VERSION 5.8 ;
BUSBITCHARS "[]" ;
DIVIDERCHAR "/" ;
UNITS
    DATABASE MICRONS 1000 ;
END UNITS

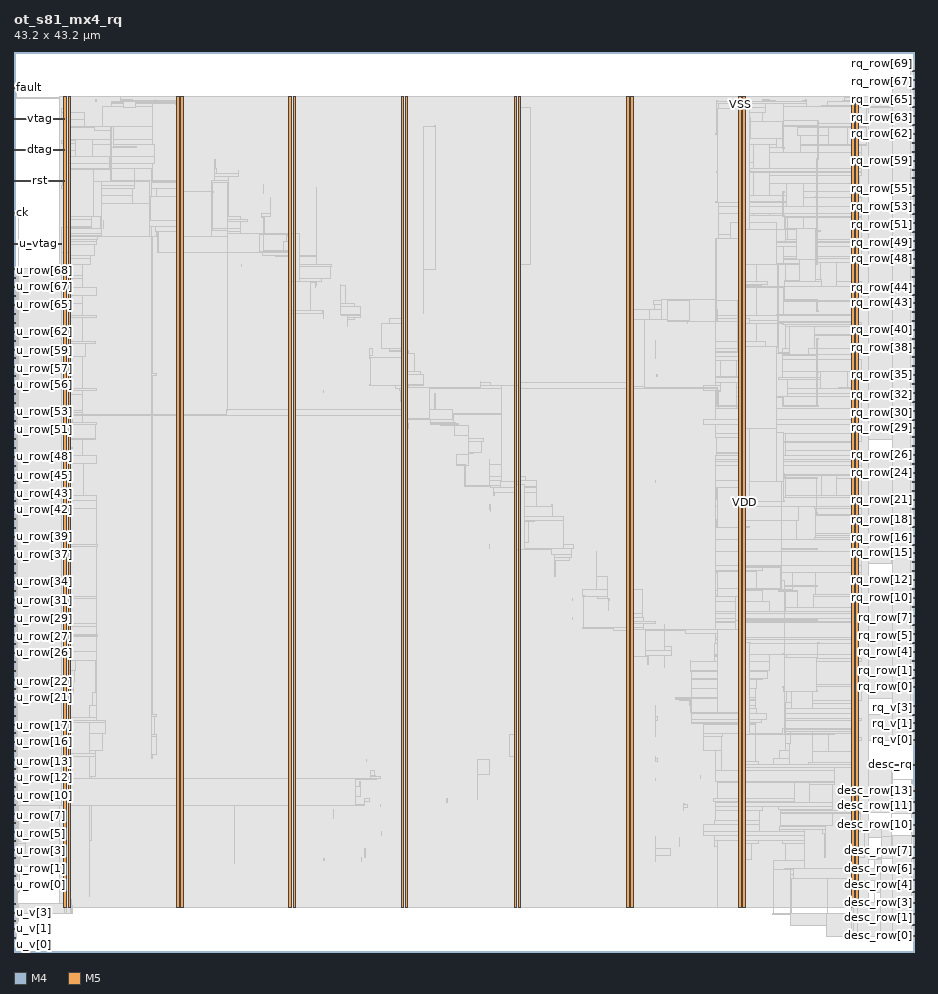
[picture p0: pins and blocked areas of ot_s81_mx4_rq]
MACRO ot_s81_mx4_rq
  FOREIGN ot_s81_mx4_rq 0 0 ;
  CLASS BLOCK ;
  SIZE 43.2 BY 43.2 ;
  PIN ck
    DIRECTION INPUT ;
    USE SIGNAL ;
    PORT
      LAYER M4 ;
        RECT  0 35.472 0.084 35.496 ;
    END
    PORT
      LAYER M4 ;
        RECT  0.06 35.472 0.227 35.496 ;
    END
  END ck
  PIN desc_row[0]
    DIRECTION INPUT ;
    USE SIGNAL ;
    PORT
      LAYER M4 ;
        RECT  43.116 0.768 43.2 0.792 ;
    END
  END desc_row[0]
  PIN desc_row[10]
    DIRECTION INPUT ;
    USE SIGNAL ;
    PORT
      LAYER M4 ;
        RECT  43.116 6.096 43.2 6.12 ;
    END
  END desc_row[10]
  PIN desc_row[11]
    DIRECTION INPUT ;
    USE SIGNAL ;
    PORT
      LAYER M4 ;
        RECT  43.116 6.672 43.2 6.696 ;
    END
  END desc_row[11]
  PIN desc_row[12]
    DIRECTION INPUT ;
    USE SIGNAL ;
    PORT
      LAYER M4 ;
        RECT  43.116 7.2 43.2 7.224 ;
    END
  END desc_row[12]
  PIN desc_row[13]
    DIRECTION INPUT ;
    USE SIGNAL ;
    PORT
      LAYER M4 ;
        RECT  43.116 7.728 43.2 7.752 ;
    END
  END desc_row[13]
  PIN desc_row[1]
    DIRECTION INPUT ;
    USE SIGNAL ;
    PORT
      LAYER M4 ;
        RECT  43.116 1.296 43.2 1.32 ;
    END
  END desc_row[1]
  PIN desc_row[2]
    DIRECTION INPUT ;
    USE SIGNAL ;
    PORT
      LAYER M4 ;
        RECT  43.116 1.824 43.2 1.848 ;
    END
  END desc_row[2]
  PIN desc_row[3]
    DIRECTION INPUT ;
    USE SIGNAL ;
    PORT
      LAYER M4 ;
        RECT  43.116 2.352 43.2 2.376 ;
    END
  END desc_row[3]
  PIN desc_row[4]
    DIRECTION INPUT ;
    USE SIGNAL ;
    PORT
      LAYER M4 ;
        RECT  43.116 2.88 43.2 2.904 ;
    END
  END desc_row[4]
  PIN desc_row[5]
    DIRECTION INPUT ;
    USE SIGNAL ;
    PORT
      LAYER M4 ;
        RECT  43.116 3.456 43.2 3.48 ;
    END
  END desc_row[5]
  PIN desc_row[6]
    DIRECTION INPUT ;
    USE SIGNAL ;
    PORT
      LAYER M4 ;
        RECT  43.116 3.984 43.2 4.008 ;
    END
  END desc_row[6]
  PIN desc_row[7]
    DIRECTION INPUT ;
    USE SIGNAL ;
    PORT
      LAYER M4 ;
        RECT  43.116 4.512 43.2 4.536 ;
    END
  END desc_row[7]
  PIN desc_row[8]
    DIRECTION INPUT ;
    USE SIGNAL ;
    PORT
      LAYER M4 ;
        RECT  43.116 5.04 43.2 5.064 ;
    END
  END desc_row[8]
  PIN desc_row[9]
    DIRECTION INPUT ;
    USE SIGNAL ;
    PORT
      LAYER M4 ;
        RECT  43.116 5.568 43.2 5.592 ;
    END
  END desc_row[9]
  PIN desc_rq
    DIRECTION INPUT ;
    USE SIGNAL ;
    PORT
      LAYER M4 ;
        RECT  43.116 8.976 43.2 9 ;
    END
    PORT
      LAYER M4 ;
        RECT  42.145 8.976 43.164 9 ;
    END
  END desc_rq
  PIN dtag
    DIRECTION OUTPUT ;
    USE SIGNAL ;
    PORT
      LAYER M4 ;
        RECT  0 38.496 0.084 38.52 ;
    END
    PORT
      LAYER M4 ;
        RECT  0.06 38.496 2.401 38.52 ;
    END
  END dtag
  PIN fault
    DIRECTION OUTPUT ;
    USE SIGNAL ;
    PORT
      LAYER M4 ;
        RECT  0 41.472 0.084 41.496 ;
    END
    PORT
      LAYER M4 ;
        RECT  0.06 41.472 0.137 41.496 ;
    END
  END fault
  PIN rq_row[0]
    DIRECTION OUTPUT ;
    USE SIGNAL ;
    PORT
      LAYER M4 ;
        RECT  43.116 12.72 43.2 12.744 ;
    END
  END rq_row[0]
  PIN rq_row[10]
    DIRECTION OUTPUT ;
    USE SIGNAL ;
    PORT
      LAYER M4 ;
        RECT  43.116 16.992 43.2 17.016 ;
    END
  END rq_row[10]
  PIN rq_row[11]
    DIRECTION OUTPUT ;
    USE SIGNAL ;
    PORT
      LAYER M4 ;
        RECT  43.116 17.424 43.2 17.448 ;
    END
  END rq_row[11]
  PIN rq_row[12]
    DIRECTION OUTPUT ;
    USE SIGNAL ;
    PORT
      LAYER M4 ;
        RECT  43.116 17.856 43.2 17.88 ;
    END
  END rq_row[12]
  PIN rq_row[13]
    DIRECTION OUTPUT ;
    USE SIGNAL ;
    PORT
      LAYER M4 ;
        RECT  43.116 18.288 43.2 18.312 ;
    END
  END rq_row[13]
  PIN rq_row[14]
    DIRECTION OUTPUT ;
    USE SIGNAL ;
    PORT
      LAYER M4 ;
        RECT  43.116 18.72 43.2 18.744 ;
    END
  END rq_row[14]
  PIN rq_row[15]
    DIRECTION OUTPUT ;
    USE SIGNAL ;
    PORT
      LAYER M4 ;
        RECT  43.116 19.152 43.2 19.176 ;
    END
  END rq_row[15]
  PIN rq_row[16]
    DIRECTION OUTPUT ;
    USE SIGNAL ;
    PORT
      LAYER M4 ;
        RECT  43.116 19.536 43.2 19.56 ;
    END
  END rq_row[16]
  PIN rq_row[17]
    DIRECTION OUTPUT ;
    USE SIGNAL ;
    PORT
      LAYER M4 ;
        RECT  43.116 19.968 43.2 19.992 ;
    END
  END rq_row[17]
  PIN rq_row[18]
    DIRECTION OUTPUT ;
    USE SIGNAL ;
    PORT
      LAYER M4 ;
        RECT  43.116 20.4 43.2 20.424 ;
    END
  END rq_row[18]
  PIN rq_row[19]
    DIRECTION OUTPUT ;
    USE SIGNAL ;
    PORT
      LAYER M4 ;
        RECT  43.116 20.832 43.2 20.856 ;
    END
  END rq_row[19]
  PIN rq_row[1]
    DIRECTION OUTPUT ;
    USE SIGNAL ;
    PORT
      LAYER M4 ;
        RECT  43.116 13.152 43.2 13.176 ;
    END
  END rq_row[1]
  PIN rq_row[20]
    DIRECTION OUTPUT ;
    USE SIGNAL ;
    PORT
      LAYER M4 ;
        RECT  43.116 21.264 43.2 21.288 ;
    END
  END rq_row[20]
  PIN rq_row[21]
    DIRECTION OUTPUT ;
    USE SIGNAL ;
    PORT
      LAYER M4 ;
        RECT  43.116 21.696 43.2 21.72 ;
    END
  END rq_row[21]
  PIN rq_row[22]
    DIRECTION OUTPUT ;
    USE SIGNAL ;
    PORT
      LAYER M4 ;
        RECT  43.116 22.128 43.2 22.152 ;
    END
  END rq_row[22]
  PIN rq_row[23]
    DIRECTION OUTPUT ;
    USE SIGNAL ;
    PORT
      LAYER M4 ;
        RECT  43.116 22.56 43.2 22.584 ;
    END
  END rq_row[23]
  PIN rq_row[24]
    DIRECTION OUTPUT ;
    USE SIGNAL ;
    PORT
      LAYER M4 ;
        RECT  43.116 22.992 43.2 23.016 ;
    END
  END rq_row[24]
  PIN rq_row[25]
    DIRECTION OUTPUT ;
    USE SIGNAL ;
    PORT
      LAYER M4 ;
        RECT  43.116 23.424 43.2 23.448 ;
    END
  END rq_row[25]
  PIN rq_row[26]
    DIRECTION OUTPUT ;
    USE SIGNAL ;
    PORT
      LAYER M4 ;
        RECT  43.116 23.856 43.2 23.88 ;
    END
  END rq_row[26]
  PIN rq_row[27]
    DIRECTION OUTPUT ;
    USE SIGNAL ;
    PORT
      LAYER M4 ;
        RECT  43.116 24.288 43.2 24.312 ;
    END
  END rq_row[27]
  PIN rq_row[28]
    DIRECTION OUTPUT ;
    USE SIGNAL ;
    PORT
      LAYER M4 ;
        RECT  43.116 24.72 43.2 24.744 ;
    END
  END rq_row[28]
  PIN rq_row[29]
    DIRECTION OUTPUT ;
    USE SIGNAL ;
    PORT
      LAYER M4 ;
        RECT  43.116 25.152 43.2 25.176 ;
    END
  END rq_row[29]
  PIN rq_row[2]
    DIRECTION OUTPUT ;
    USE SIGNAL ;
    PORT
      LAYER M4 ;
        RECT  43.116 13.536 43.2 13.56 ;
    END
  END rq_row[2]
  PIN rq_row[30]
    DIRECTION OUTPUT ;
    USE SIGNAL ;
    PORT
      LAYER M4 ;
        RECT  43.116 25.536 43.2 25.56 ;
    END
  END rq_row[30]
  PIN rq_row[31]
    DIRECTION OUTPUT ;
    USE SIGNAL ;
    PORT
      LAYER M4 ;
        RECT  43.116 25.968 43.2 25.992 ;
    END
  END rq_row[31]
  PIN rq_row[32]
    DIRECTION OUTPUT ;
    USE SIGNAL ;
    PORT
      LAYER M4 ;
        RECT  43.116 26.4 43.2 26.424 ;
    END
  END rq_row[32]
  PIN rq_row[33]
    DIRECTION OUTPUT ;
    USE SIGNAL ;
    PORT
      LAYER M4 ;
        RECT  43.116 26.832 43.2 26.856 ;
    END
  END rq_row[33]
  PIN rq_row[34]
    DIRECTION OUTPUT ;
    USE SIGNAL ;
    PORT
      LAYER M4 ;
        RECT  43.116 27.264 43.2 27.288 ;
    END
  END rq_row[34]
  PIN rq_row[35]
    DIRECTION OUTPUT ;
    USE SIGNAL ;
    PORT
      LAYER M4 ;
        RECT  43.116 27.696 43.2 27.72 ;
    END
  END rq_row[35]
  PIN rq_row[36]
    DIRECTION OUTPUT ;
    USE SIGNAL ;
    PORT
      LAYER M4 ;
        RECT  43.116 28.128 43.2 28.152 ;
    END
  END rq_row[36]
  PIN rq_row[37]
    DIRECTION OUTPUT ;
    USE SIGNAL ;
    PORT
      LAYER M4 ;
        RECT  43.116 28.56 43.2 28.584 ;
    END
  END rq_row[37]
  PIN rq_row[38]
    DIRECTION OUTPUT ;
    USE SIGNAL ;
    PORT
      LAYER M4 ;
        RECT  43.116 28.992 43.2 29.016 ;
    END
  END rq_row[38]
  PIN rq_row[39]
    DIRECTION OUTPUT ;
    USE SIGNAL ;
    PORT
      LAYER M4 ;
        RECT  43.116 29.424 43.2 29.448 ;
    END
  END rq_row[39]
  PIN rq_row[3]
    DIRECTION OUTPUT ;
    USE SIGNAL ;
    PORT
      LAYER M4 ;
        RECT  43.116 13.968 43.2 13.992 ;
    END
  END rq_row[3]
  PIN rq_row[40]
    DIRECTION OUTPUT ;
    USE SIGNAL ;
    PORT
      LAYER M4 ;
        RECT  43.116 29.856 43.2 29.88 ;
    END
  END rq_row[40]
  PIN rq_row[41]
    DIRECTION OUTPUT ;
    USE SIGNAL ;
    PORT
      LAYER M4 ;
        RECT  43.116 30.288 43.2 30.312 ;
    END
  END rq_row[41]
  PIN rq_row[42]
    DIRECTION OUTPUT ;
    USE SIGNAL ;
    PORT
      LAYER M4 ;
        RECT  43.116 30.72 43.2 30.744 ;
    END
  END rq_row[42]
  PIN rq_row[43]
    DIRECTION OUTPUT ;
    USE SIGNAL ;
    PORT
      LAYER M4 ;
        RECT  43.116 31.152 43.2 31.176 ;
    END
  END rq_row[43]
  PIN rq_row[44]
    DIRECTION OUTPUT ;
    USE SIGNAL ;
    PORT
      LAYER M4 ;
        RECT  43.116 31.536 43.2 31.56 ;
    END
  END rq_row[44]
  PIN rq_row[45]
    DIRECTION OUTPUT ;
    USE SIGNAL ;
    PORT
      LAYER M4 ;
        RECT  43.116 31.968 43.2 31.992 ;
    END
  END rq_row[45]
  PIN rq_row[46]
    DIRECTION OUTPUT ;
    USE SIGNAL ;
    PORT
      LAYER M4 ;
        RECT  43.116 32.4 43.2 32.424 ;
    END
  END rq_row[46]
  PIN rq_row[47]
    DIRECTION OUTPUT ;
    USE SIGNAL ;
    PORT
      LAYER M4 ;
        RECT  43.116 32.832 43.2 32.856 ;
    END
  END rq_row[47]
  PIN rq_row[48]
    DIRECTION OUTPUT ;
    USE SIGNAL ;
    PORT
      LAYER M4 ;
        RECT  43.116 33.264 43.2 33.288 ;
    END
  END rq_row[48]
  PIN rq_row[49]
    DIRECTION OUTPUT ;
    USE SIGNAL ;
    PORT
      LAYER M4 ;
        RECT  43.116 33.696 43.2 33.72 ;
    END
  END rq_row[49]
  PIN rq_row[4]
    DIRECTION OUTPUT ;
    USE SIGNAL ;
    PORT
      LAYER M4 ;
        RECT  43.116 14.4 43.2 14.424 ;
    END
  END rq_row[4]
  PIN rq_row[50]
    DIRECTION OUTPUT ;
    USE SIGNAL ;
    PORT
      LAYER M4 ;
        RECT  43.116 34.128 43.2 34.152 ;
    END
  END rq_row[50]
  PIN rq_row[51]
    DIRECTION OUTPUT ;
    USE SIGNAL ;
    PORT
      LAYER M4 ;
        RECT  43.116 34.56 43.2 34.584 ;
    END
  END rq_row[51]
  PIN rq_row[52]
    DIRECTION OUTPUT ;
    USE SIGNAL ;
    PORT
      LAYER M4 ;
        RECT  43.116 34.992 43.2 35.016 ;
    END
  END rq_row[52]
  PIN rq_row[53]
    DIRECTION OUTPUT ;
    USE SIGNAL ;
    PORT
      LAYER M4 ;
        RECT  43.116 35.424 43.2 35.448 ;
    END
  END rq_row[53]
  PIN rq_row[54]
    DIRECTION OUTPUT ;
    USE SIGNAL ;
    PORT
      LAYER M4 ;
        RECT  43.116 35.856 43.2 35.88 ;
    END
  END rq_row[54]
  PIN rq_row[55]
    DIRECTION OUTPUT ;
    USE SIGNAL ;
    PORT
      LAYER M4 ;
        RECT  43.116 36.288 43.2 36.312 ;
    END
  END rq_row[55]
  PIN rq_row[56]
    DIRECTION OUTPUT ;
    USE SIGNAL ;
    PORT
      LAYER M4 ;
        RECT  43.116 36.72 43.2 36.744 ;
    END
  END rq_row[56]
  PIN rq_row[57]
    DIRECTION OUTPUT ;
    USE SIGNAL ;
    PORT
      LAYER M4 ;
        RECT  43.116 37.152 43.2 37.176 ;
    END
  END rq_row[57]
  PIN rq_row[58]
    DIRECTION OUTPUT ;
    USE SIGNAL ;
    PORT
      LAYER M4 ;
        RECT  43.116 37.536 43.2 37.56 ;
    END
  END rq_row[58]
  PIN rq_row[59]
    DIRECTION OUTPUT ;
    USE SIGNAL ;
    PORT
      LAYER M4 ;
        RECT  43.116 37.968 43.2 37.992 ;
    END
  END rq_row[59]
  PIN rq_row[5]
    DIRECTION OUTPUT ;
    USE SIGNAL ;
    PORT
      LAYER M4 ;
        RECT  43.116 14.832 43.2 14.856 ;
    END
  END rq_row[5]
  PIN rq_row[60]
    DIRECTION OUTPUT ;
    USE SIGNAL ;
    PORT
      LAYER M4 ;
        RECT  43.116 38.4 43.2 38.424 ;
    END
  END rq_row[60]
  PIN rq_row[61]
    DIRECTION OUTPUT ;
    USE SIGNAL ;
    PORT
      LAYER M4 ;
        RECT  43.116 38.832 43.2 38.856 ;
    END
  END rq_row[61]
  PIN rq_row[62]
    DIRECTION OUTPUT ;
    USE SIGNAL ;
    PORT
      LAYER M4 ;
        RECT  43.116 39.264 43.2 39.288 ;
    END
  END rq_row[62]
  PIN rq_row[63]
    DIRECTION OUTPUT ;
    USE SIGNAL ;
    PORT
      LAYER M4 ;
        RECT  43.116 39.696 43.2 39.72 ;
    END
  END rq_row[63]
  PIN rq_row[64]
    DIRECTION OUTPUT ;
    USE SIGNAL ;
    PORT
      LAYER M4 ;
        RECT  43.116 40.128 43.2 40.152 ;
    END
  END rq_row[64]
  PIN rq_row[65]
    DIRECTION OUTPUT ;
    USE SIGNAL ;
    PORT
      LAYER M4 ;
        RECT  43.116 40.56 43.2 40.584 ;
    END
  END rq_row[65]
  PIN rq_row[66]
    DIRECTION OUTPUT ;
    USE SIGNAL ;
    PORT
      LAYER M4 ;
        RECT  43.116 40.992 43.2 41.016 ;
    END
  END rq_row[66]
  PIN rq_row[67]
    DIRECTION OUTPUT ;
    USE SIGNAL ;
    PORT
      LAYER M4 ;
        RECT  43.116 41.424 43.2 41.448 ;
    END
  END rq_row[67]
  PIN rq_row[68]
    DIRECTION OUTPUT ;
    USE SIGNAL ;
    PORT
      LAYER M4 ;
        RECT  43.116 41.856 43.2 41.88 ;
    END
  END rq_row[68]
  PIN rq_row[69]
    DIRECTION OUTPUT ;
    USE SIGNAL ;
    PORT
      LAYER M4 ;
        RECT  43.116 42.288 43.2 42.312 ;
    END
  END rq_row[69]
  PIN rq_row[6]
    DIRECTION OUTPUT ;
    USE SIGNAL ;
    PORT
      LAYER M4 ;
        RECT  43.116 15.264 43.2 15.288 ;
    END
  END rq_row[6]
  PIN rq_row[7]
    DIRECTION OUTPUT ;
    USE SIGNAL ;
    PORT
      LAYER M4 ;
        RECT  43.116 15.696 43.2 15.72 ;
    END
  END rq_row[7]
  PIN rq_row[8]
    DIRECTION OUTPUT ;
    USE SIGNAL ;
    PORT
      LAYER M4 ;
        RECT  43.116 16.128 43.2 16.152 ;
    END
  END rq_row[8]
  PIN rq_row[9]
    DIRECTION OUTPUT ;
    USE SIGNAL ;
    PORT
      LAYER M4 ;
        RECT  43.116 16.56 43.2 16.584 ;
    END
  END rq_row[9]
  PIN rq_v[0]
    DIRECTION OUTPUT ;
    USE SIGNAL ;
    PORT
      LAYER M4 ;
        RECT  43.116 10.176 43.2 10.2 ;
    END
  END rq_v[0]
  PIN rq_v[1]
    DIRECTION OUTPUT ;
    USE SIGNAL ;
    PORT
      LAYER M4 ;
        RECT  43.116 10.608 43.2 10.632 ;
    END
  END rq_v[1]
  PIN rq_v[2]
    DIRECTION OUTPUT ;
    USE SIGNAL ;
    PORT
      LAYER M4 ;
        RECT  43.116 10.992 43.2 11.016 ;
    END
  END rq_v[2]
  PIN rq_v[3]
    DIRECTION OUTPUT ;
    USE SIGNAL ;
    PORT
      LAYER M4 ;
        RECT  43.116 11.376 43.2 11.4 ;
    END
  END rq_v[3]
  PIN rq_v[4]
    DIRECTION OUTPUT ;
    USE SIGNAL ;
    PORT
      LAYER M4 ;
        RECT  43.116 11.808 43.2 11.832 ;
    END
  END rq_v[4]
  PIN rst
    DIRECTION INPUT ;
    USE SIGNAL ;
    PORT
      LAYER M4 ;
        RECT  0 37.008 0.084 37.032 ;
    END
    PORT
      LAYER M4 ;
        RECT  0.06 37.008 2.401 37.032 ;
    END
  END rst
  PIN u_row[0]
    DIRECTION INPUT ;
    USE SIGNAL ;
    PORT
      LAYER M4 ;
        RECT  0 3.216 0.084 3.24 ;
    END
  END u_row[0]
  PIN u_row[10]
    DIRECTION INPUT ;
    USE SIGNAL ;
    PORT
      LAYER M4 ;
        RECT  0 7.488 0.084 7.512 ;
    END
  END u_row[10]
  PIN u_row[11]
    DIRECTION INPUT ;
    USE SIGNAL ;
    PORT
      LAYER M4 ;
        RECT  0 7.92 0.084 7.944 ;
    END
  END u_row[11]
  PIN u_row[12]
    DIRECTION INPUT ;
    USE SIGNAL ;
    PORT
      LAYER M4 ;
        RECT  0 8.352 0.084 8.376 ;
    END
  END u_row[12]
  PIN u_row[13]
    DIRECTION INPUT ;
    USE SIGNAL ;
    PORT
      LAYER M4 ;
        RECT  0 8.784 0.084 8.808 ;
    END
  END u_row[13]
  PIN u_row[14]
    DIRECTION INPUT ;
    USE SIGNAL ;
    PORT
      LAYER M4 ;
        RECT  0 9.216 0.084 9.24 ;
    END
  END u_row[14]
  PIN u_row[15]
    DIRECTION INPUT ;
    USE SIGNAL ;
    PORT
      LAYER M4 ;
        RECT  0 9.648 0.084 9.672 ;
    END
  END u_row[15]
  PIN u_row[16]
    DIRECTION INPUT ;
    USE SIGNAL ;
    PORT
      LAYER M4 ;
        RECT  0 10.08 0.084 10.104 ;
    END
  END u_row[16]
  PIN u_row[17]
    DIRECTION INPUT ;
    USE SIGNAL ;
    PORT
      LAYER M4 ;
        RECT  0 10.512 0.084 10.536 ;
    END
  END u_row[17]
  PIN u_row[18]
    DIRECTION INPUT ;
    USE SIGNAL ;
    PORT
      LAYER M4 ;
        RECT  0 10.896 0.084 10.92 ;
    END
  END u_row[18]
  PIN u_row[19]
    DIRECTION INPUT ;
    USE SIGNAL ;
    PORT
      LAYER M4 ;
        RECT  0 11.328 0.084 11.352 ;
    END
  END u_row[19]
  PIN u_row[1]
    DIRECTION INPUT ;
    USE SIGNAL ;
    PORT
      LAYER M4 ;
        RECT  0 3.648 0.084 3.672 ;
    END
  END u_row[1]
  PIN u_row[20]
    DIRECTION INPUT ;
    USE SIGNAL ;
    PORT
      LAYER M4 ;
        RECT  0 11.76 0.084 11.784 ;
    END
  END u_row[20]
  PIN u_row[21]
    DIRECTION INPUT ;
    USE SIGNAL ;
    PORT
      LAYER M4 ;
        RECT  0 12.192 0.084 12.216 ;
    END
  END u_row[21]
  PIN u_row[22]
    DIRECTION INPUT ;
    USE SIGNAL ;
    PORT
      LAYER M4 ;
        RECT  0 12.624 0.084 12.648 ;
    END
  END u_row[22]
  PIN u_row[23]
    DIRECTION INPUT ;
    USE SIGNAL ;
    PORT
      LAYER M4 ;
        RECT  0 13.056 0.084 13.08 ;
    END
  END u_row[23]
  PIN u_row[24]
    DIRECTION INPUT ;
    USE SIGNAL ;
    PORT
      LAYER M4 ;
        RECT  0 13.488 0.084 13.512 ;
    END
  END u_row[24]
  PIN u_row[25]
    DIRECTION INPUT ;
    USE SIGNAL ;
    PORT
      LAYER M4 ;
        RECT  0 13.92 0.084 13.944 ;
    END
  END u_row[25]
  PIN u_row[26]
    DIRECTION INPUT ;
    USE SIGNAL ;
    PORT
      LAYER M4 ;
        RECT  0 14.352 0.084 14.376 ;
    END
  END u_row[26]
  PIN u_row[27]
    DIRECTION INPUT ;
    USE SIGNAL ;
    PORT
      LAYER M4 ;
        RECT  0 14.784 0.084 14.808 ;
    END
  END u_row[27]
  PIN u_row[28]
    DIRECTION INPUT ;
    USE SIGNAL ;
    PORT
      LAYER M4 ;
        RECT  0 15.216 0.084 15.24 ;
    END
  END u_row[28]
  PIN u_row[29]
    DIRECTION INPUT ;
    USE SIGNAL ;
    PORT
      LAYER M4 ;
        RECT  0 15.648 0.084 15.672 ;
    END
  END u_row[29]
  PIN u_row[2]
    DIRECTION INPUT ;
    USE SIGNAL ;
    PORT
      LAYER M4 ;
        RECT  0 4.08 0.084 4.104 ;
    END
  END u_row[2]
  PIN u_row[30]
    DIRECTION INPUT ;
    USE SIGNAL ;
    PORT
      LAYER M4 ;
        RECT  0 16.08 0.084 16.104 ;
    END
  END u_row[30]
  PIN u_row[31]
    DIRECTION INPUT ;
    USE SIGNAL ;
    PORT
      LAYER M4 ;
        RECT  0 16.512 0.084 16.536 ;
    END
  END u_row[31]
  PIN u_row[32]
    DIRECTION INPUT ;
    USE SIGNAL ;
    PORT
      LAYER M4 ;
        RECT  0 16.896 0.084 16.92 ;
    END
  END u_row[32]
  PIN u_row[33]
    DIRECTION INPUT ;
    USE SIGNAL ;
    PORT
      LAYER M4 ;
        RECT  0 17.328 0.084 17.352 ;
    END
  END u_row[33]
  PIN u_row[34]
    DIRECTION INPUT ;
    USE SIGNAL ;
    PORT
      LAYER M4 ;
        RECT  0 17.76 0.084 17.784 ;
    END
  END u_row[34]
  PIN u_row[35]
    DIRECTION INPUT ;
    USE SIGNAL ;
    PORT
      LAYER M4 ;
        RECT  0 18.192 0.084 18.216 ;
    END
  END u_row[35]
  PIN u_row[36]
    DIRECTION INPUT ;
    USE SIGNAL ;
    PORT
      LAYER M4 ;
        RECT  0 18.624 0.084 18.648 ;
    END
  END u_row[36]
  PIN u_row[37]
    DIRECTION INPUT ;
    USE SIGNAL ;
    PORT
      LAYER M4 ;
        RECT  0 19.056 0.084 19.08 ;
    END
  END u_row[37]
  PIN u_row[38]
    DIRECTION INPUT ;
    USE SIGNAL ;
    PORT
      LAYER M4 ;
        RECT  0 19.488 0.084 19.512 ;
    END
  END u_row[38]
  PIN u_row[39]
    DIRECTION INPUT ;
    USE SIGNAL ;
    PORT
      LAYER M4 ;
        RECT  0 19.92 0.084 19.944 ;
    END
  END u_row[39]
  PIN u_row[3]
    DIRECTION INPUT ;
    USE SIGNAL ;
    PORT
      LAYER M4 ;
        RECT  0 4.512 0.084 4.536 ;
    END
  END u_row[3]
  PIN u_row[40]
    DIRECTION INPUT ;
    USE SIGNAL ;
    PORT
      LAYER M4 ;
        RECT  0 20.352 0.084 20.376 ;
    END
  END u_row[40]
  PIN u_row[41]
    DIRECTION INPUT ;
    USE SIGNAL ;
    PORT
      LAYER M4 ;
        RECT  0 20.784 0.084 20.808 ;
    END
  END u_row[41]
  PIN u_row[42]
    DIRECTION INPUT ;
    USE SIGNAL ;
    PORT
      LAYER M4 ;
        RECT  0 21.216 0.084 21.24 ;
    END
  END u_row[42]
  PIN u_row[43]
    DIRECTION INPUT ;
    USE SIGNAL ;
    PORT
      LAYER M4 ;
        RECT  0 21.648 0.084 21.672 ;
    END
  END u_row[43]
  PIN u_row[44]
    DIRECTION INPUT ;
    USE SIGNAL ;
    PORT
      LAYER M4 ;
        RECT  0 22.08 0.084 22.104 ;
    END
  END u_row[44]
  PIN u_row[45]
    DIRECTION INPUT ;
    USE SIGNAL ;
    PORT
      LAYER M4 ;
        RECT  0 22.512 0.084 22.536 ;
    END
  END u_row[45]
  PIN u_row[46]
    DIRECTION INPUT ;
    USE SIGNAL ;
    PORT
      LAYER M4 ;
        RECT  0 22.896 0.084 22.92 ;
    END
  END u_row[46]
  PIN u_row[47]
    DIRECTION INPUT ;
    USE SIGNAL ;
    PORT
      LAYER M4 ;
        RECT  0 23.328 0.084 23.352 ;
    END
  END u_row[47]
  PIN u_row[48]
    DIRECTION INPUT ;
    USE SIGNAL ;
    PORT
      LAYER M4 ;
        RECT  0 23.76 0.084 23.784 ;
    END
  END u_row[48]
  PIN u_row[49]
    DIRECTION INPUT ;
    USE SIGNAL ;
    PORT
      LAYER M4 ;
        RECT  0 24.192 0.084 24.216 ;
    END
  END u_row[49]
  PIN u_row[4]
    DIRECTION INPUT ;
    USE SIGNAL ;
    PORT
      LAYER M4 ;
        RECT  0 4.896 0.084 4.92 ;
    END
  END u_row[4]
  PIN u_row[50]
    DIRECTION INPUT ;
    USE SIGNAL ;
    PORT
      LAYER M4 ;
        RECT  0 24.624 0.084 24.648 ;
    END
  END u_row[50]
  PIN u_row[51]
    DIRECTION INPUT ;
    USE SIGNAL ;
    PORT
      LAYER M4 ;
        RECT  0 25.056 0.084 25.08 ;
    END
  END u_row[51]
  PIN u_row[52]
    DIRECTION INPUT ;
    USE SIGNAL ;
    PORT
      LAYER M4 ;
        RECT  0 25.488 0.084 25.512 ;
    END
  END u_row[52]
  PIN u_row[53]
    DIRECTION INPUT ;
    USE SIGNAL ;
    PORT
      LAYER M4 ;
        RECT  0 25.92 0.084 25.944 ;
    END
  END u_row[53]
  PIN u_row[54]
    DIRECTION INPUT ;
    USE SIGNAL ;
    PORT
      LAYER M4 ;
        RECT  0 26.352 0.084 26.376 ;
    END
  END u_row[54]
  PIN u_row[55]
    DIRECTION INPUT ;
    USE SIGNAL ;
    PORT
      LAYER M4 ;
        RECT  0 26.784 0.084 26.808 ;
    END
  END u_row[55]
  PIN u_row[56]
    DIRECTION INPUT ;
    USE SIGNAL ;
    PORT
      LAYER M4 ;
        RECT  0 27.216 0.084 27.24 ;
    END
  END u_row[56]
  PIN u_row[57]
    DIRECTION INPUT ;
    USE SIGNAL ;
    PORT
      LAYER M4 ;
        RECT  0 27.648 0.084 27.672 ;
    END
  END u_row[57]
  PIN u_row[58]
    DIRECTION INPUT ;
    USE SIGNAL ;
    PORT
      LAYER M4 ;
        RECT  0 28.08 0.084 28.104 ;
    END
  END u_row[58]
  PIN u_row[59]
    DIRECTION INPUT ;
    USE SIGNAL ;
    PORT
      LAYER M4 ;
        RECT  0 28.512 0.084 28.536 ;
    END
  END u_row[59]
  PIN u_row[5]
    DIRECTION INPUT ;
    USE SIGNAL ;
    PORT
      LAYER M4 ;
        RECT  0 5.328 0.084 5.352 ;
    END
  END u_row[5]
  PIN u_row[60]
    DIRECTION INPUT ;
    USE SIGNAL ;
    PORT
      LAYER M4 ;
        RECT  0 28.896 0.084 28.92 ;
    END
  END u_row[60]
  PIN u_row[61]
    DIRECTION INPUT ;
    USE SIGNAL ;
    PORT
      LAYER M4 ;
        RECT  0 29.328 0.084 29.352 ;
    END
  END u_row[61]
  PIN u_row[62]
    DIRECTION INPUT ;
    USE SIGNAL ;
    PORT
      LAYER M4 ;
        RECT  0 29.76 0.084 29.784 ;
    END
  END u_row[62]
  PIN u_row[63]
    DIRECTION INPUT ;
    USE SIGNAL ;
    PORT
      LAYER M4 ;
        RECT  0 30.192 0.084 30.216 ;
    END
  END u_row[63]
  PIN u_row[64]
    DIRECTION INPUT ;
    USE SIGNAL ;
    PORT
      LAYER M4 ;
        RECT  0 30.624 0.084 30.648 ;
    END
  END u_row[64]
  PIN u_row[65]
    DIRECTION INPUT ;
    USE SIGNAL ;
    PORT
      LAYER M4 ;
        RECT  0 31.056 0.084 31.08 ;
    END
  END u_row[65]
  PIN u_row[66]
    DIRECTION INPUT ;
    USE SIGNAL ;
    PORT
      LAYER M4 ;
        RECT  0 31.488 0.084 31.512 ;
    END
  END u_row[66]
  PIN u_row[67]
    DIRECTION INPUT ;
    USE SIGNAL ;
    PORT
      LAYER M4 ;
        RECT  0 31.92 0.084 31.944 ;
    END
  END u_row[67]
  PIN u_row[68]
    DIRECTION INPUT ;
    USE SIGNAL ;
    PORT
      LAYER M4 ;
        RECT  0 32.352 0.084 32.376 ;
    END
  END u_row[68]
  PIN u_row[69]
    DIRECTION INPUT ;
    USE SIGNAL ;
    PORT
      LAYER M4 ;
        RECT  0 32.784 0.084 32.808 ;
    END
  END u_row[69]
  PIN u_row[6]
    DIRECTION INPUT ;
    USE SIGNAL ;
    PORT
      LAYER M4 ;
        RECT  0 5.76 0.084 5.784 ;
    END
  END u_row[6]
  PIN u_row[7]
    DIRECTION INPUT ;
    USE SIGNAL ;
    PORT
      LAYER M4 ;
        RECT  0 6.192 0.084 6.216 ;
    END
  END u_row[7]
  PIN u_row[8]
    DIRECTION INPUT ;
    USE SIGNAL ;
    PORT
      LAYER M4 ;
        RECT  0 6.624 0.084 6.648 ;
    END
  END u_row[8]
  PIN u_row[9]
    DIRECTION INPUT ;
    USE SIGNAL ;
    PORT
      LAYER M4 ;
        RECT  0 7.056 0.084 7.08 ;
    END
  END u_row[9]
  PIN u_v[0]
    DIRECTION INPUT ;
    USE SIGNAL ;
    PORT
      LAYER M4 ;
        RECT  0 0.672 0.084 0.696 ;
    END
  END u_v[0]
  PIN u_v[1]
    DIRECTION INPUT ;
    USE SIGNAL ;
    PORT
      LAYER M4 ;
        RECT  0 1.104 0.084 1.128 ;
    END
  END u_v[1]
  PIN u_v[2]
    DIRECTION INPUT ;
    USE SIGNAL ;
    PORT
      LAYER M4 ;
        RECT  0 1.488 0.084 1.512 ;
    END
  END u_v[2]
  PIN u_v[3]
    DIRECTION INPUT ;
    USE SIGNAL ;
    PORT
      LAYER M4 ;
        RECT  0 1.872 0.084 1.896 ;
    END
  END u_v[3]
  PIN u_v[4]
    DIRECTION INPUT ;
    USE SIGNAL ;
    PORT
      LAYER M4 ;
        RECT  0 2.304 0.084 2.328 ;
    END
  END u_v[4]
  PIN u_vtag
    DIRECTION INPUT ;
    USE SIGNAL ;
    PORT
      LAYER M4 ;
        RECT  0 33.984 0.084 34.008 ;
    END
    PORT
      LAYER M4 ;
        RECT  0.06 33.984 2.293 34.008 ;
    END
  END u_vtag
  PIN vtag
    DIRECTION OUTPUT ;
    USE SIGNAL ;
    PORT
      LAYER M4 ;
        RECT  0 39.984 0.084 40.008 ;
    END
    PORT
      LAYER M4 ;
        RECT  0.06 39.984 2.408 40.008 ;
    END
  END vtag
  PIN VDD
    DIRECTION INOUT ;
    USE POWER ;
    PORT
      LAYER M5 ;
        RECT  40.392 2.151 40.512 41.049 ;
        RECT  34.992 2.151 35.112 41.049 ;
        RECT  29.592 2.151 29.712 41.049 ;
        RECT  24.192 2.151 24.312 41.049 ;
        RECT  18.792 2.151 18.912 41.049 ;
        RECT  13.392 2.151 13.512 41.049 ;
        RECT  7.992 2.151 8.112 41.049 ;
        RECT  2.592 2.151 2.712 41.049 ;
    END
  END VDD
  PIN VSS
    DIRECTION INOUT ;
    USE GROUND ;
    PORT
      LAYER M5 ;
        RECT  40.2 2.137 40.32 41.063 ;
        RECT  34.8 2.137 34.92 41.063 ;
        RECT  29.4 2.137 29.52 41.063 ;
        RECT  24 2.137 24.12 41.063 ;
        RECT  18.6 2.137 18.72 41.063 ;
        RECT  13.2 2.137 13.32 41.063 ;
        RECT  7.8 2.137 7.92 41.063 ;
        RECT  2.4 2.137 2.52 41.063 ;
    END
  END VSS
  # OT_OBS_CLOSED layer=M5 d_um=1.536 added=19
  OBS
    LAYER RVTN ;
     RECT  2.16 2.16 41.04 2.295 ;
     RECT  2.16 2.565 41.04 2.835 ;
     RECT  2.16 3.105 41.04 3.375 ;
     RECT  2.16 3.645 41.04 3.915 ;
     RECT  2.16 4.185 41.04 4.455 ;
     RECT  2.16 4.725 41.04 4.995 ;
     RECT  2.16 5.265 41.04 5.535 ;
     RECT  2.16 5.805 41.04 6.075 ;
     RECT  2.16 6.345 41.04 6.615 ;
     RECT  2.16 6.885 41.04 7.155 ;
     RECT  2.16 7.425 41.04 7.695 ;
     RECT  2.16 7.965 41.04 8.235 ;
     RECT  2.16 8.505 41.04 8.775 ;
     RECT  2.16 9.045 41.04 9.315 ;
     RECT  2.16 9.585 41.04 9.855 ;
     RECT  2.16 10.125 41.04 10.395 ;
     RECT  2.16 10.665 41.04 10.935 ;
     RECT  2.16 11.205 41.04 11.475 ;
     RECT  2.16 11.745 41.04 12.015 ;
     RECT  2.16 12.285 41.04 12.555 ;
     RECT  2.16 12.825 41.04 13.095 ;
     RECT  2.16 13.365 41.04 13.635 ;
     RECT  2.16 13.905 41.04 14.175 ;
     RECT  2.16 14.445 41.04 14.715 ;
     RECT  2.16 14.985 41.04 15.255 ;
     RECT  2.16 15.525 41.04 15.795 ;
     RECT  2.16 16.065 41.04 16.335 ;
     RECT  2.16 16.605 41.04 16.875 ;
     RECT  2.16 17.145 41.04 17.415 ;
     RECT  2.16 17.685 41.04 17.955 ;
     RECT  2.16 18.225 41.04 18.495 ;
     RECT  2.16 18.765 41.04 19.035 ;
     RECT  2.16 19.305 41.04 19.575 ;
     RECT  2.16 19.845 41.04 20.115 ;
     RECT  2.16 20.385 41.04 20.655 ;
     RECT  2.16 20.925 41.04 21.195 ;
     RECT  2.16 21.465 41.04 21.735 ;
     RECT  2.16 22.005 41.04 22.275 ;
     RECT  2.16 22.545 41.04 22.815 ;
     RECT  2.16 23.085 41.04 23.355 ;
     RECT  2.16 23.625 41.04 23.895 ;
     RECT  2.16 24.165 41.04 24.435 ;
     RECT  2.16 24.705 41.04 24.975 ;
     RECT  2.16 25.245 41.04 25.515 ;
     RECT  2.16 25.785 41.04 26.055 ;
     RECT  2.16 26.325 41.04 26.595 ;
     RECT  2.16 26.865 41.04 27.135 ;
     RECT  2.16 27.405 41.04 27.675 ;
     RECT  2.16 27.945 41.04 28.215 ;
     RECT  2.16 28.485 41.04 28.755 ;
     RECT  2.16 29.025 41.04 29.295 ;
     RECT  2.16 29.565 41.04 29.835 ;
     RECT  2.16 30.105 41.04 30.375 ;
     RECT  2.16 30.645 41.04 30.915 ;
     RECT  2.16 31.185 41.04 31.455 ;
     RECT  2.16 31.725 41.04 31.995 ;
     RECT  2.16 32.265 41.04 32.535 ;
     RECT  2.16 32.805 41.04 33.075 ;
     RECT  2.16 33.345 41.04 33.615 ;
     RECT  2.16 33.885 41.04 34.155 ;
     RECT  2.16 34.425 41.04 34.695 ;
     RECT  2.16 34.965 41.04 35.235 ;
     RECT  2.16 35.505 41.04 35.775 ;
     RECT  2.16 36.045 41.04 36.315 ;
     RECT  2.16 36.585 41.04 36.855 ;
     RECT  2.16 37.125 41.04 37.395 ;
     RECT  2.16 37.665 41.04 37.935 ;
     RECT  2.16 38.205 41.04 38.475 ;
     RECT  2.16 38.745 41.04 39.015 ;
     RECT  2.16 39.285 41.04 39.555 ;
     RECT  2.16 39.825 41.04 40.095 ;
     RECT  2.16 40.365 41.04 40.635 ;
     RECT  2.16 40.905 41.04 41.04 ;
    LAYER RVTP ;
     RECT  2.16 2.295 41.04 2.565 ;
     RECT  2.16 2.835 41.04 3.105 ;
     RECT  2.16 3.375 41.04 3.645 ;
     RECT  2.16 3.915 41.04 4.185 ;
     RECT  2.16 4.455 41.04 4.725 ;
     RECT  2.16 4.995 41.04 5.265 ;
     RECT  2.16 5.535 41.04 5.805 ;
     RECT  2.16 6.075 41.04 6.345 ;
     RECT  2.16 6.615 41.04 6.885 ;
     RECT  2.16 7.155 41.04 7.425 ;
     RECT  2.16 7.695 41.04 7.965 ;
     RECT  2.16 8.235 41.04 8.505 ;
     RECT  2.16 8.775 41.04 9.045 ;
     RECT  2.16 9.315 41.04 9.585 ;
     RECT  2.16 9.855 41.04 10.125 ;
     RECT  2.16 10.395 41.04 10.665 ;
     RECT  2.16 10.935 41.04 11.205 ;
     RECT  2.16 11.475 41.04 11.745 ;
     RECT  2.16 12.015 41.04 12.285 ;
     RECT  2.16 12.555 41.04 12.825 ;
     RECT  2.16 13.095 41.04 13.365 ;
     RECT  2.16 13.635 41.04 13.905 ;
     RECT  2.16 14.175 41.04 14.445 ;
     RECT  2.16 14.715 41.04 14.985 ;
     RECT  2.16 15.255 41.04 15.525 ;
     RECT  2.16 15.795 41.04 16.065 ;
     RECT  2.16 16.335 41.04 16.605 ;
     RECT  2.16 16.875 41.04 17.145 ;
     RECT  2.16 17.415 41.04 17.685 ;
     RECT  2.16 17.955 41.04 18.225 ;
     RECT  2.16 18.495 41.04 18.765 ;
     RECT  2.16 19.035 41.04 19.305 ;
     RECT  2.16 19.575 41.04 19.845 ;
     RECT  2.16 20.115 41.04 20.385 ;
     RECT  2.16 20.655 41.04 20.925 ;
     RECT  2.16 21.195 41.04 21.465 ;
     RECT  2.16 21.735 41.04 22.005 ;
     RECT  2.16 22.275 41.04 22.545 ;
     RECT  2.16 22.815 41.04 23.085 ;
     RECT  2.16 23.355 41.04 23.625 ;
     RECT  2.16 23.895 41.04 24.165 ;
     RECT  2.16 24.435 41.04 24.705 ;
     RECT  2.16 24.975 41.04 25.245 ;
     RECT  2.16 25.515 41.04 25.785 ;
     RECT  2.16 26.055 41.04 26.325 ;
     RECT  2.16 26.595 41.04 26.865 ;
     RECT  2.16 27.135 41.04 27.405 ;
     RECT  2.16 27.675 41.04 27.945 ;
     RECT  2.16 28.215 41.04 28.485 ;
     RECT  2.16 28.755 41.04 29.025 ;
     RECT  2.16 29.295 41.04 29.565 ;
     RECT  2.16 29.835 41.04 30.105 ;
     RECT  2.16 30.375 41.04 30.645 ;
     RECT  2.16 30.915 41.04 31.185 ;
     RECT  2.16 31.455 41.04 31.725 ;
     RECT  2.16 31.995 41.04 32.265 ;
     RECT  2.16 32.535 41.04 32.805 ;
     RECT  2.16 33.075 41.04 33.345 ;
     RECT  2.16 33.615 41.04 33.885 ;
     RECT  2.16 34.155 41.04 34.425 ;
     RECT  2.16 34.695 41.04 34.965 ;
     RECT  2.16 35.235 41.04 35.505 ;
     RECT  2.16 35.775 41.04 36.045 ;
     RECT  2.16 36.315 41.04 36.585 ;
     RECT  2.16 36.855 41.04 37.125 ;
     RECT  2.16 37.395 41.04 37.665 ;
     RECT  2.16 37.935 41.04 38.205 ;
     RECT  2.16 38.475 41.04 38.745 ;
     RECT  2.16 39.015 41.04 39.285 ;
     RECT  2.16 39.555 41.04 39.825 ;
     RECT  2.16 40.095 41.04 40.365 ;
     RECT  2.16 40.635 41.04 40.905 ;
    LAYER M1 ;
     RECT  2.16 2.151 41.04 41.049 ;
    LAYER M2 ;
     RECT  0.067 5.202 0.103 5.22 ;
     RECT  0.103 2.844 0.139 2.862 ;
     RECT  0.103 4.392 0.139 4.41 ;
     RECT  0.103 5.202 0.139 5.49 ;
     RECT  0.103 6.282 0.139 6.3 ;
     RECT  0.103 7.092 0.139 7.11 ;
     RECT  0.139 4.356 0.175 4.41 ;
     RECT  0.139 5.202 0.175 7.11 ;
     RECT  0.175 4.356 0.211 7.11 ;
     RECT  0.139 2.844 0.239 2.934 ;
     RECT  0.239 2.916 0.275 2.934 ;
     RECT  0.211 4.122 2.16 7.11 ;
     RECT  0.103 8.28 2.16 8.298 ;
     RECT  0.103 9.324 2.16 9.342 ;
     RECT  0.103 40.986 2.16 41.004 ;
     RECT  2.16 2.151 41.04 41.049 ;
     RECT  41.04 4.428 41.315 4.518 ;
     RECT  41.315 4.5 41.639 4.518 ;
     RECT  41.04 5.508 41.639 5.868 ;
     RECT  41.04 6.696 42.143 9.036 ;
     RECT  41.639 5.508 42.179 5.526 ;
     RECT  42.143 7.668 42.179 9.036 ;
     RECT  41.04 10.17 42.179 11.394 ;
     RECT  41.04 12.186 42.179 17.874 ;
     RECT  41.04 18.666 42.179 23.814 ;
     RECT  41.04 24.606 42.179 35.964 ;
     RECT  41.04 36.756 42.179 41.004 ;
     RECT  42.179 39.528 42.215 40.464 ;
     RECT  42.215 39.528 43.079 40.194 ;
     RECT  42.143 6.894 43.115 6.912 ;
     RECT  42.179 8.28 43.115 8.298 ;
     RECT  42.179 16.506 43.115 16.524 ;
     RECT  42.179 21.636 43.115 21.654 ;
     RECT  42.179 26.766 43.115 26.784 ;
     RECT  42.179 31.896 43.115 31.914 ;
     RECT  42.179 35.856 43.115 35.874 ;
     RECT  43.079 39.528 43.115 39.546 ;
    LAYER M3 ;
     RECT  0.108 0.667 0.126 1.099 ;
     RECT  0.108 1.099 0.162 1.483 ;
     RECT  0.108 1.483 0.198 1.579 ;
     RECT  0.072 1.579 0.198 1.613 ;
     RECT  2.772 1.867 2.79 2.143 ;
     RECT  2.415 2.143 2.79 2.255 ;
     RECT  7.815 2.143 7.905 2.413 ;
     RECT  13.215 2.143 13.305 2.413 ;
     RECT  18.615 2.143 18.705 2.413 ;
     RECT  24.015 2.143 24.105 2.413 ;
     RECT  29.415 2.143 29.505 2.413 ;
     RECT  34.815 2.143 34.905 2.413 ;
     RECT  40.215 2.143 40.305 2.413 ;
     RECT  2.415 2.255 2.754 2.525 ;
     RECT  0.072 1.613 0.162 2.839 ;
     RECT  41.292 2.347 41.31 2.875 ;
     RECT  0.072 2.839 0.234 2.911 ;
     RECT  40.215 2.413 40.497 3.451 ;
     RECT  41.292 2.875 41.634 3.451 ;
     RECT  37.296 1.291 37.314 3.547 ;
     RECT  40.215 3.451 41.634 3.569 ;
     RECT  39.024 0.763 39.042 3.605 ;
     RECT  37.296 3.547 37.422 3.721 ;
     RECT  36.432 1.819 36.45 3.979 ;
     RECT  37.296 3.721 37.962 3.979 ;
     RECT  36.432 3.979 37.962 4.415 ;
     RECT  34.815 2.413 35.097 4.423 ;
     RECT  41.292 3.569 41.634 4.451 ;
     RECT  14.868 4.387 14.886 4.487 ;
     RECT  0.072 2.911 0.27 4.507 ;
     RECT  41.616 4.451 41.634 4.507 ;
     RECT  16.668 4.351 16.686 4.523 ;
     RECT  40.215 3.569 40.497 4.531 ;
     RECT  30.78 4.351 30.798 4.621 ;
     RECT  16.848 4.531 16.866 4.955 ;
     RECT  30.78 4.621 31.518 4.955 ;
     RECT  33.768 2.191 33.786 5.071 ;
     RECT  2.415 2.525 2.697 5.197 ;
     RECT  34.815 4.423 35.406 5.197 ;
     RECT  37.008 4.415 37.962 5.197 ;
     RECT  0.072 4.507 0.558 5.225 ;
     RECT  0.108 5.225 0.558 5.297 ;
     RECT  2.376 5.197 2.697 5.297 ;
     RECT  3.6 2.641 3.618 5.341 ;
     RECT  33.624 5.071 33.786 5.341 ;
     RECT  34.815 5.197 35.73 5.341 ;
     RECT  36.9 5.197 37.962 5.341 ;
     RECT  31.932 5.071 31.95 5.495 ;
     RECT  41.616 4.507 42.174 5.531 ;
     RECT  30.78 4.955 30.798 5.567 ;
     RECT  33.624 5.341 37.962 5.611 ;
     RECT  38.916 4.531 38.934 5.701 ;
     RECT  17.64 5.611 17.658 5.765 ;
     RECT  33.084 5.611 37.962 5.801 ;
     RECT  40.215 4.531 40.842 5.801 ;
     RECT  41.616 5.531 42.138 5.873 ;
     RECT  36.756 5.801 37.962 5.881 ;
     RECT  38.808 5.701 38.934 5.881 ;
     RECT  36.756 5.881 38.934 6.035 ;
     RECT  36.792 6.035 38.934 6.079 ;
     RECT  33.084 5.801 35.802 6.107 ;
     RECT  33.624 6.107 35.802 6.305 ;
     RECT  0.108 5.297 0.162 6.575 ;
     RECT  36.792 6.079 39.294 6.655 ;
     RECT  40.215 5.801 40.626 6.655 ;
     RECT  42.12 5.873 42.138 6.667 ;
     RECT  36.792 6.655 40.626 6.683 ;
     RECT  33.66 6.305 35.802 6.781 ;
     RECT  36.792 6.683 40.497 6.809 ;
     RECT  15.336 6.421 15.354 6.845 ;
     RECT  36.792 6.809 39.294 6.853 ;
     RECT  43.092 6.091 43.11 6.917 ;
     RECT  32.112 6.781 32.13 6.925 ;
     RECT  33.66 6.781 35.946 6.961 ;
     RECT  36.684 6.853 39.294 6.961 ;
     RECT  2.415 5.297 2.697 7.051 ;
     RECT  13.215 2.413 13.497 7.051 ;
     RECT  17.568 6.961 17.586 7.079 ;
     RECT  32.112 6.925 32.31 7.079 ;
     RECT  0.108 6.575 0.126 7.115 ;
     RECT  32.112 7.079 32.202 7.115 ;
     RECT  32.184 7.115 32.202 7.151 ;
     RECT  33.66 6.961 39.294 7.187 ;
     RECT  10.584 4.261 10.602 7.223 ;
     RECT  16.812 7.051 16.83 7.231 ;
     RECT  33.66 7.187 37.458 7.231 ;
     RECT  16.812 7.231 17.046 7.349 ;
     RECT  16.812 7.349 16.83 7.385 ;
     RECT  20.772 7.195 20.79 7.385 ;
     RECT  33.552 7.231 37.458 7.385 ;
     RECT  42.12 6.667 42.174 7.385 ;
     RECT  2.304 7.051 2.697 7.529 ;
     RECT  13.104 7.051 13.497 7.529 ;
     RECT  42.156 7.385 42.174 7.691 ;
     RECT  16.38 7.483 16.614 7.925 ;
     RECT  38.196 7.187 39.294 8.041 ;
     RECT  33.768 7.385 37.458 8.131 ;
     RECT  38.196 8.041 39.366 8.131 ;
     RECT  16.596 7.925 16.614 8.195 ;
     RECT  33.768 8.131 39.366 8.203 ;
     RECT  2.415 7.529 2.697 8.299 ;
     RECT  17.1 8.275 17.118 8.299 ;
     RECT  43.092 7.723 43.11 8.303 ;
     RECT  17.1 8.299 17.37 8.311 ;
     RECT  2.415 8.299 2.79 8.339 ;
     RECT  30.78 8.239 30.798 8.339 ;
     RECT  3.6 5.341 3.726 8.401 ;
     RECT  17.1 8.311 17.586 8.429 ;
     RECT  17.1 8.429 17.37 8.465 ;
     RECT  32.94 8.311 32.958 8.465 ;
     RECT  22.248 7.321 22.266 8.509 ;
     RECT  33.696 8.203 39.366 8.699 ;
     RECT  17.1 8.465 17.298 8.735 ;
     RECT  34.815 8.699 39.366 8.851 ;
     RECT  40.215 6.809 40.497 8.851 ;
     RECT  34.815 8.851 40.497 9.005 ;
     RECT  42.156 8.971 42.174 9.041 ;
     RECT  38.16 9.005 40.497 9.077 ;
     RECT  38.304 9.077 40.497 9.113 ;
     RECT  34.815 9.005 35.73 9.149 ;
     RECT  2.415 8.339 2.697 9.211 ;
     RECT  16.92 9.121 16.938 9.239 ;
     RECT  22.248 8.509 22.806 9.239 ;
     RECT  36.468 9.005 37.206 9.275 ;
     RECT  30.78 9.121 30.87 9.311 ;
     RECT  0.108 7.915 0.126 9.347 ;
     RECT  30.78 9.311 30.798 9.383 ;
     RECT  2.304 9.211 2.697 9.391 ;
     RECT  3.6 8.401 3.906 9.391 ;
     RECT  24.015 2.413 24.297 9.391 ;
     RECT  6.624 9.283 6.642 9.481 ;
     RECT  2.304 9.391 3.906 9.509 ;
     RECT  38.34 9.113 40.497 9.617 ;
     RECT  3.6 9.509 3.906 9.661 ;
     RECT  33.696 8.699 33.966 9.661 ;
     RECT  36.756 9.275 37.206 9.689 ;
     RECT  2.304 9.509 2.697 9.815 ;
     RECT  37.008 9.689 37.206 10.021 ;
     RECT  40.215 9.617 40.497 10.165 ;
     RECT  40.215 10.165 40.698 10.319 ;
     RECT  6.624 9.481 6.822 10.363 ;
     RECT  33.12 9.661 33.966 10.363 ;
     RECT  23.76 9.391 24.297 10.427 ;
     RECT  38.34 9.617 39.114 10.435 ;
     RECT  6.624 10.363 6.858 10.463 ;
     RECT  3.6 9.661 4.266 10.471 ;
     RECT  33.12 10.363 34.002 10.471 ;
     RECT  34.815 9.149 35.586 10.471 ;
     RECT  38.34 10.435 39.402 10.471 ;
     RECT  40.215 10.319 40.554 10.471 ;
     RECT  37.008 10.021 37.278 10.597 ;
     RECT  38.34 10.471 40.554 10.597 ;
     RECT  37.008 10.597 40.554 10.669 ;
     RECT  36.9 10.669 40.554 10.733 ;
     RECT  33.12 10.471 35.586 10.939 ;
     RECT  33.084 10.939 35.586 10.975 ;
     RECT  2.34 9.815 2.697 11.011 ;
     RECT  3.6 10.471 4.41 11.011 ;
     RECT  32.544 10.975 35.586 11.011 ;
     RECT  30.78 10.363 30.798 11.101 ;
     RECT  37.008 10.733 40.554 11.101 ;
     RECT  2.34 11.011 4.41 11.129 ;
     RECT  32.544 11.011 35.874 11.137 ;
     RECT  37.008 11.101 40.698 11.201 ;
     RECT  2.34 11.129 3.942 11.237 ;
     RECT  6.624 10.463 6.75 11.281 ;
     RECT  30.78 11.101 30.87 11.309 ;
     RECT  2.34 11.237 2.697 11.323 ;
     RECT  6.624 11.281 6.822 11.399 ;
     RECT  32.544 11.137 36.126 11.435 ;
     RECT  37.008 11.201 40.497 11.435 ;
     RECT  37.044 11.435 40.497 11.669 ;
     RECT  32.544 11.435 35.622 11.705 ;
     RECT  2.304 11.323 2.697 11.813 ;
     RECT  32.544 11.705 35.586 11.821 ;
     RECT  3.6 11.237 3.942 11.849 ;
     RECT  30.78 11.309 30.798 11.849 ;
     RECT  38.34 11.669 40.497 11.947 ;
     RECT  37.044 11.669 37.314 11.975 ;
     RECT  32.436 11.821 35.586 12.091 ;
     RECT  38.34 11.947 40.554 12.091 ;
     RECT  31.932 12.091 35.586 12.139 ;
     RECT  31.752 12.139 35.586 12.209 ;
     RECT  2.412 11.813 2.697 12.361 ;
     RECT  3.78 11.849 3.942 12.479 ;
     RECT  2.412 12.361 2.862 12.619 ;
     RECT  32.508 12.209 35.586 12.631 ;
     RECT  37.08 11.975 37.314 12.715 ;
     RECT  36.936 12.715 37.314 12.755 ;
     RECT  37.08 12.755 37.314 12.757 ;
     RECT  38.34 12.091 40.698 12.757 ;
     RECT  37.08 12.757 40.698 12.821 ;
     RECT  2.304 12.619 2.862 12.991 ;
     RECT  32.508 12.631 35.622 13.099 ;
     RECT  32.508 13.099 35.946 13.135 ;
     RECT  3.924 12.479 3.942 13.261 ;
     RECT  32.508 13.135 36.162 13.441 ;
     RECT  2.304 12.991 2.898 13.531 ;
     RECT  32.472 13.441 36.162 13.531 ;
     RECT  32.472 13.531 36.27 13.937 ;
     RECT  37.08 12.821 40.497 13.945 ;
     RECT  32.472 13.937 32.49 13.973 ;
     RECT  2.304 13.531 2.97 13.981 ;
     RECT  3.888 13.261 3.942 13.981 ;
     RECT  37.08 13.945 40.698 14.099 ;
     RECT  29.415 2.413 29.697 14.203 ;
     RECT  30.42 13.801 30.438 14.203 ;
     RECT  29.415 14.203 30.438 14.215 ;
     RECT  31.212 13.675 31.23 14.215 ;
     RECT  29.415 14.215 31.23 14.251 ;
     RECT  33.624 13.937 36.27 14.299 ;
     RECT  37.08 14.099 40.554 14.299 ;
     RECT  2.304 13.981 3.942 14.405 ;
     RECT  29.415 14.251 31.554 14.477 ;
     RECT  31.212 14.477 31.554 14.675 ;
     RECT  33.624 14.299 40.554 14.819 ;
     RECT  33.66 14.819 40.554 14.989 ;
     RECT  33.66 14.989 40.698 15.089 ;
     RECT  2.415 14.405 3.942 15.151 ;
     RECT  2.415 15.151 4.014 15.211 ;
     RECT  2.412 15.211 4.014 15.251 ;
     RECT  29.415 14.477 30.222 15.331 ;
     RECT  32.22 15.307 32.238 15.331 ;
     RECT  29.376 15.331 30.222 15.451 ;
     RECT  32.22 15.331 32.49 15.485 ;
     RECT  28.8 15.451 30.222 15.581 ;
     RECT  2.412 15.251 3.978 15.643 ;
     RECT  31.212 14.675 31.23 15.719 ;
     RECT  29.376 15.581 30.222 15.763 ;
     RECT  2.304 15.643 3.978 15.791 ;
     RECT  33.66 15.089 40.497 15.835 ;
     RECT  29.376 15.763 30.798 15.863 ;
     RECT  33.66 15.835 40.554 15.871 ;
     RECT  33.66 15.871 40.698 16.025 ;
     RECT  26.784 15.961 26.802 16.061 ;
     RECT  29.376 15.863 30.222 16.061 ;
     RECT  29.376 16.061 30.186 16.259 ;
     RECT  33.66 16.025 40.554 16.259 ;
     RECT  42.156 10.165 42.174 16.259 ;
     RECT  33.66 16.259 40.497 16.331 ;
     RECT  37.044 16.331 40.497 16.529 ;
     RECT  43.092 16.501 43.11 16.589 ;
     RECT  33.66 16.331 36.27 16.835 ;
     RECT  28.512 16.411 28.53 16.879 ;
     RECT  2.304 15.791 3.942 16.951 ;
     RECT  28.512 16.879 28.602 16.951 ;
     RECT  26.784 16.879 26.802 16.979 ;
     RECT  28.008 16.951 28.602 16.979 ;
     RECT  38.376 16.529 40.497 17.041 ;
     RECT  2.304 16.951 3.978 17.069 ;
     RECT  28.008 16.979 28.494 17.083 ;
     RECT  38.376 17.041 40.698 17.141 ;
     RECT  37.044 16.529 37.602 17.311 ;
     RECT  36.684 17.311 37.602 17.339 ;
     RECT  33.66 16.835 35.91 17.375 ;
     RECT  27.288 17.083 28.494 17.411 ;
     RECT  29.415 16.259 30.186 17.411 ;
     RECT  36.684 17.339 37.386 17.411 ;
     RECT  29.415 17.411 29.754 17.681 ;
     RECT  27.936 17.411 28.494 18.023 ;
     RECT  36.792 17.411 37.386 18.193 ;
     RECT  38.448 17.141 40.698 18.193 ;
     RECT  33.66 17.375 35.658 18.257 ;
     RECT  33.696 18.257 35.658 18.301 ;
     RECT  33.696 18.301 35.946 18.535 ;
     RECT  36.792 18.193 40.698 18.535 ;
     RECT  42.156 16.987 42.174 18.715 ;
     RECT  25.956 18.031 25.974 18.805 ;
     RECT  25.956 18.805 26.658 18.931 ;
     RECT  25.956 18.931 26.766 19.075 ;
     RECT  27.936 18.023 27.954 19.229 ;
     RECT  33.696 18.535 40.698 19.229 ;
     RECT  25.776 19.075 26.766 19.373 ;
     RECT  26.352 19.373 26.766 19.381 ;
     RECT  2.304 17.069 3.942 19.471 ;
     RECT  2.304 19.471 4.014 19.571 ;
     RECT  22.824 19.381 22.842 19.571 ;
     RECT  26.352 19.381 26.838 19.571 ;
     RECT  24.015 10.427 24.297 19.651 ;
     RECT  42.12 18.715 42.174 19.769 ;
     RECT  33.696 19.229 40.554 19.805 ;
     RECT  38.412 19.805 40.554 19.877 ;
     RECT  38.448 19.877 40.554 20.011 ;
     RECT  38.448 20.011 40.698 20.111 ;
     RECT  24.015 19.651 24.714 20.659 ;
     RECT  24.015 20.659 25.002 20.695 ;
     RECT  33.696 19.805 37.566 20.695 ;
     RECT  24.015 20.695 25.254 20.731 ;
     RECT  26.352 19.571 26.37 20.731 ;
     RECT  24.015 20.731 26.37 20.921 ;
     RECT  38.448 20.111 40.497 20.965 ;
     RECT  38.448 20.965 40.518 21.001 ;
     RECT  22.86 21.163 22.878 21.262 ;
     RECT  2.304 19.571 3.942 21.271 ;
     RECT  38.448 21.001 40.698 21.271 ;
     RECT  24.015 20.921 25.83 21.389 ;
     RECT  33.696 20.695 37.674 21.397 ;
     RECT  38.412 21.271 40.698 21.397 ;
     RECT  22.824 21.262 22.878 21.461 ;
     RECT  25.812 21.389 25.83 21.461 ;
     RECT  2.304 21.271 3.978 21.659 ;
     RECT  43.092 21.631 43.11 21.725 ;
     RECT  33.696 21.397 40.698 21.803 ;
     RECT  2.304 21.659 3.942 21.929 ;
     RECT  33.696 21.803 36.162 21.929 ;
     RECT  37.008 21.803 40.698 21.929 ;
     RECT  23.04 21.901 23.058 22.045 ;
     RECT  24.015 21.389 25.074 22.045 ;
     RECT  23.04 22.045 25.074 22.315 ;
     RECT  22.896 22.315 25.074 22.351 ;
     RECT  22.824 22.351 25.074 22.613 ;
     RECT  30.78 22.513 30.798 22.613 ;
     RECT  33.696 21.929 36.126 22.637 ;
     RECT  39.492 21.929 40.698 22.739 ;
     RECT  22.824 22.613 24.57 22.811 ;
     RECT  37.008 21.929 38.754 22.855 ;
     RECT  39.492 22.739 40.662 22.855 ;
     RECT  37.008 22.855 40.662 22.939 ;
     RECT  33.696 22.637 35.946 23.359 ;
     RECT  36.936 22.939 40.662 23.359 ;
     RECT  21.816 23.359 21.834 23.371 ;
     RECT  22.824 22.811 24.297 23.387 ;
     RECT  2.304 21.929 3.33 23.431 ;
     RECT  33.696 23.359 40.662 23.521 ;
     RECT  22.824 23.387 22.842 23.621 ;
     RECT  33.696 23.521 40.698 23.621 ;
     RECT  2.304 23.431 3.978 23.819 ;
     RECT  33.696 23.621 40.497 23.819 ;
     RECT  2.304 23.819 3.294 23.855 ;
     RECT  33.732 23.819 40.497 23.855 ;
     RECT  21.24 23.371 21.834 23.891 ;
     RECT  21.816 23.891 21.834 23.935 ;
     RECT  21.816 23.935 22.05 23.971 ;
     RECT  37.008 23.855 40.497 24.089 ;
     RECT  37.044 24.089 40.497 24.475 ;
     RECT  21.816 23.971 22.446 24.511 ;
     RECT  37.044 24.475 40.554 24.511 ;
     RECT  2.415 23.855 3.294 24.601 ;
     RECT  2.415 24.601 3.906 24.619 ;
     RECT  2.304 24.619 3.906 24.665 ;
     RECT  21.816 24.511 22.518 24.665 ;
     RECT  33.732 23.855 36.27 24.673 ;
     RECT  21.816 24.665 21.834 24.781 ;
     RECT  33.696 24.673 36.27 24.907 ;
     RECT  37.044 24.511 40.698 24.907 ;
     RECT  18.615 2.413 18.897 25.141 ;
     RECT  21.168 24.781 21.834 25.249 ;
     RECT  20.448 25.249 21.834 25.277 ;
     RECT  2.415 24.665 3.906 25.321 ;
     RECT  20.448 25.277 21.33 25.321 ;
     RECT  33.696 24.907 40.698 25.321 ;
     RECT  18.615 25.141 18.954 25.349 ;
     RECT  19.98 25.321 21.33 25.349 ;
     RECT  2.415 25.321 3.978 25.439 ;
     RECT  19.98 25.349 21.186 25.439 ;
     RECT  19.98 25.439 21.078 25.555 ;
     RECT  19.908 25.555 21.078 25.579 ;
     RECT  33.12 25.321 40.698 25.583 ;
     RECT  19.836 25.579 21.078 25.619 ;
     RECT  19.908 25.619 21.042 25.661 ;
     RECT  2.415 25.439 3.294 25.915 ;
     RECT  2.304 25.915 3.294 26.015 ;
     RECT  19.98 25.661 21.042 26.015 ;
     RECT  21.024 26.015 21.042 26.045 ;
     RECT  33.696 25.583 40.698 26.087 ;
     RECT  18.615 25.349 18.897 26.131 ;
     RECT  18.615 26.131 18.954 26.401 ;
     RECT  33.696 26.087 33.822 26.491 ;
     RECT  42.156 19.769 42.174 26.519 ;
     RECT  34.668 26.087 40.698 26.669 ;
     RECT  2.415 26.015 3.294 26.779 ;
     RECT  20.196 26.015 20.214 26.825 ;
     RECT  37.116 26.669 40.698 26.825 ;
     RECT  43.092 26.761 43.11 26.861 ;
     RECT  33.66 26.491 33.822 26.905 ;
     RECT  2.304 26.779 3.294 26.941 ;
     RECT  18.54 26.401 18.954 26.941 ;
     RECT  33.66 26.905 33.894 26.941 ;
     RECT  14.832 26.869 14.85 26.969 ;
     RECT  2.304 26.941 3.978 27.059 ;
     RECT  37.116 26.825 40.497 27.059 ;
     RECT  18.504 26.941 18.954 27.067 ;
     RECT  34.668 26.669 36.27 27.095 ;
     RECT  39.564 27.059 40.497 27.095 ;
     RECT  22.86 27.031 22.878 27.163 ;
     RECT  24.015 23.387 24.297 27.163 ;
     RECT  18.324 27.067 18.954 27.175 ;
     RECT  33.084 26.941 33.894 27.203 ;
     RECT  18.324 27.175 19.206 27.211 ;
     RECT  18.324 27.211 19.638 27.245 ;
     RECT  22.392 27.163 22.878 27.329 ;
     RECT  33.66 27.203 33.894 27.337 ;
     RECT  34.668 27.095 35.658 27.337 ;
     RECT  24.015 27.163 24.39 27.341 ;
     RECT  22.392 27.329 22.41 27.365 ;
     RECT  37.116 27.059 38.718 27.481 ;
     RECT  33.66 27.337 35.658 27.599 ;
     RECT  36.72 27.481 38.718 27.599 ;
     RECT  33.696 27.599 35.658 27.635 ;
     RECT  6.624 11.399 6.642 27.679 ;
     RECT  18.615 27.245 19.638 27.743 ;
     RECT  30.852 27.643 30.87 27.743 ;
     RECT  6.624 27.679 6.822 27.779 ;
     RECT  40.032 27.095 40.497 27.841 ;
     RECT  18.615 27.743 19.494 27.869 ;
     RECT  36.9 27.599 38.718 27.877 ;
     RECT  40.032 27.841 40.698 27.877 ;
     RECT  33.696 27.635 33.894 28.381 ;
     RECT  34.668 27.635 35.658 28.381 ;
     RECT  36.9 27.877 40.698 28.445 ;
     RECT  2.304 27.059 3.294 28.561 ;
     RECT  33.696 28.381 35.658 28.561 ;
     RECT  17.064 28.507 17.082 28.651 ;
     RECT  36.9 28.445 40.497 28.685 ;
     RECT  36.9 28.685 37.242 28.747 ;
     RECT  18.615 27.869 19.242 28.751 ;
     RECT  36.576 28.747 37.242 28.787 ;
     RECT  33.696 28.561 35.802 28.795 ;
     RECT  18.615 28.751 18.954 28.831 ;
     RECT  18 28.831 18.954 28.859 ;
     RECT  17.064 28.651 17.226 28.949 ;
     RECT  33.696 28.795 36.162 28.949 ;
     RECT  36.9 28.787 37.242 28.949 ;
     RECT  38.16 28.685 40.497 28.949 ;
     RECT  18 28.859 18.897 28.957 ;
     RECT  37.008 28.949 37.242 28.985 ;
     RECT  2.304 28.561 3.438 29.191 ;
     RECT  2.304 29.191 3.906 29.291 ;
     RECT  33.696 28.949 36.054 29.291 ;
     RECT  30.78 28.489 30.798 29.363 ;
     RECT  38.412 28.949 40.497 29.605 ;
     RECT  38.412 29.605 40.554 29.641 ;
     RECT  37.044 28.985 37.242 30.037 ;
     RECT  38.412 29.641 40.698 30.037 ;
     RECT  37.044 30.037 40.698 30.109 ;
     RECT  17.64 28.957 18.897 30.173 ;
     RECT  36.9 30.109 40.698 30.209 ;
     RECT  32.328 30.181 32.346 30.271 ;
     RECT  33.696 29.291 35.658 30.271 ;
     RECT  36.9 30.209 40.497 30.271 ;
     RECT  32.328 30.271 32.454 30.299 ;
     RECT  15.984 30.001 16.002 30.379 ;
     RECT  18 30.173 18.897 30.407 ;
     RECT  31.356 30.283 31.374 30.413 ;
     RECT  2.304 29.291 3.294 30.451 ;
     RECT  15.984 30.379 16.326 30.451 ;
     RECT  15.984 30.451 16.65 30.541 ;
     RECT  2.304 30.451 3.978 30.569 ;
     RECT  33.696 30.271 40.497 30.569 ;
     RECT  36.576 30.569 40.497 30.605 ;
     RECT  15.696 30.541 16.65 30.613 ;
     RECT  14.832 30.415 14.85 30.797 ;
     RECT  32.436 30.299 32.454 30.845 ;
     RECT  15.66 30.613 16.65 30.983 ;
     RECT  30.744 30.811 31.086 31.081 ;
     RECT  15.66 30.983 16.362 31.109 ;
     RECT  2.304 30.569 3.294 31.145 ;
     RECT  36.936 30.605 40.497 31.225 ;
     RECT  36.936 31.225 40.554 31.261 ;
     RECT  30.708 31.081 31.086 31.289 ;
     RECT  31.068 31.289 31.086 31.325 ;
     RECT  2.415 31.145 3.294 31.531 ;
     RECT  42.156 27.259 42.174 31.649 ;
     RECT  2.415 31.531 3.978 31.915 ;
     RECT  2.412 31.915 3.978 31.919 ;
     RECT  36.936 31.261 40.698 31.949 ;
     RECT  36.972 31.949 40.698 31.955 ;
     RECT  15.66 31.109 15.894 31.991 ;
     RECT  43.092 31.891 43.11 31.997 ;
     RECT  14.472 31.891 14.49 31.999 ;
     RECT  33.696 30.569 35.658 31.999 ;
     RECT  15.66 31.991 15.678 32.027 ;
     RECT  33.696 31.999 35.874 32.035 ;
     RECT  13.215 7.529 13.497 32.155 ;
     RECT  14.472 31.999 14.526 32.155 ;
     RECT  33.696 32.035 36.162 32.189 ;
     RECT  36.972 31.955 38.754 32.189 ;
     RECT  39.492 31.955 40.698 32.189 ;
     RECT  13.215 32.155 14.526 32.197 ;
     RECT  36.972 32.189 37.71 32.225 ;
     RECT  38.448 32.189 38.754 32.261 ;
     RECT  13.215 32.197 14.742 32.341 ;
     RECT  2.412 31.919 3.294 32.347 ;
     RECT  2.304 32.347 3.294 32.495 ;
     RECT  19.656 30.649 19.674 32.737 ;
     RECT  13.215 32.341 15.174 32.881 ;
     RECT  10.908 32.881 10.926 32.999 ;
     RECT  13.215 32.881 15.246 32.999 ;
     RECT  2.376 32.495 3.294 33.007 ;
     RECT  24.015 27.341 24.297 33.007 ;
     RECT  37.044 32.225 37.71 33.019 ;
     RECT  36.648 33.019 37.71 33.071 ;
     RECT  38.448 32.261 38.718 33.115 ;
     RECT  39.492 32.189 40.497 33.115 ;
     RECT  2.376 33.007 3.69 33.277 ;
     RECT  36.936 33.071 37.71 33.277 ;
     RECT  38.448 33.115 40.497 33.277 ;
     RECT  13.215 32.999 14.526 33.385 ;
     RECT  36.936 33.277 40.497 33.385 ;
     RECT  12.528 33.385 14.526 33.413 ;
     RECT  2.34 33.277 3.69 33.421 ;
     RECT  12.528 33.413 13.497 33.421 ;
     RECT  11.916 33.421 13.497 33.583 ;
     RECT  11.736 33.583 13.497 33.629 ;
     RECT  11.952 33.629 13.497 33.683 ;
     RECT  33.696 32.189 35.658 33.817 ;
     RECT  33.696 33.817 36.126 33.853 ;
     RECT  36.936 33.385 40.698 33.853 ;
     RECT  2.34 33.421 3.87 33.961 ;
     RECT  2.34 33.961 3.942 33.979 ;
     RECT  33.696 33.853 40.698 34.079 ;
     RECT  2.304 33.979 3.942 34.115 ;
     RECT  12.924 33.683 13.497 34.115 ;
     RECT  33.732 34.079 40.698 34.115 ;
     RECT  37.044 34.115 40.698 34.187 ;
     RECT  2.415 34.115 3.942 34.195 ;
     RECT  33.732 34.115 36.27 34.253 ;
     RECT  2.415 34.195 4.014 34.321 ;
     RECT  2.415 34.321 4.23 34.357 ;
     RECT  13.104 34.115 13.497 34.385 ;
     RECT  2.415 34.357 4.914 34.393 ;
     RECT  33.804 34.253 36.27 34.421 ;
     RECT  10.26 34.363 10.278 34.429 ;
     RECT  10.26 34.429 10.566 34.459 ;
     RECT  2.415 34.393 5.058 34.501 ;
     RECT  11.952 33.683 11.97 34.501 ;
     RECT  6.624 27.779 6.642 34.603 ;
     RECT  10.26 34.459 10.854 34.603 ;
     RECT  10.224 34.603 10.854 34.733 ;
     RECT  2.415 34.501 5.49 34.771 ;
     RECT  2.415 34.771 5.526 34.843 ;
     RECT  10.26 34.733 10.854 35.041 ;
     RECT  6.624 34.603 6.858 35.117 ;
     RECT  2.415 34.843 5.778 35.159 ;
     RECT  10.26 35.041 11.214 35.159 ;
     RECT  11.952 34.501 12.006 35.275 ;
     RECT  37.044 34.187 37.134 35.275 ;
     RECT  37.872 34.187 40.698 35.275 ;
     RECT  10.26 35.159 10.854 35.303 ;
     RECT  11.88 35.275 12.006 35.311 ;
     RECT  36.252 34.421 36.27 35.311 ;
     RECT  37.044 35.275 40.698 35.311 ;
     RECT  11.88 35.311 12.33 35.429 ;
     RECT  33.804 34.421 35.478 35.437 ;
     RECT  36.252 35.311 40.698 35.437 ;
     RECT  33.804 35.437 40.698 35.771 ;
     RECT  6.624 35.117 6.642 35.899 ;
     RECT  42.156 32.395 42.174 35.969 ;
     RECT  33.804 35.771 37.098 35.977 ;
     RECT  33.732 35.977 37.098 36.029 ;
     RECT  6.624 35.899 6.822 36.235 ;
     RECT  12.312 35.429 12.33 36.239 ;
     RECT  37.872 35.771 40.698 36.239 ;
     RECT  6.552 36.235 6.822 36.275 ;
     RECT  33.804 36.029 37.098 36.311 ;
     RECT  43.092 35.851 43.11 36.317 ;
     RECT  2.415 35.159 5.67 36.319 ;
     RECT  37.872 36.239 40.626 36.509 ;
     RECT  2.415 36.319 5.706 36.625 ;
     RECT  2.34 36.625 5.706 36.661 ;
     RECT  6.624 36.275 6.822 36.661 ;
     RECT  7.815 2.413 8.097 36.661 ;
     RECT  14.508 33.413 14.526 36.689 ;
     RECT  2.304 36.661 5.778 36.815 ;
     RECT  11.952 36.391 11.97 36.851 ;
     RECT  36.252 36.311 37.098 36.895 ;
     RECT  37.872 36.509 40.59 36.895 ;
     RECT  9.504 36.475 9.522 36.931 ;
     RECT  10.26 35.303 10.278 36.931 ;
     RECT  6.624 36.661 8.097 36.959 ;
     RECT  2.34 36.815 5.778 37.037 ;
     RECT  6.624 36.959 6.858 37.037 ;
     RECT  9.504 36.931 10.278 37.049 ;
     RECT  9.648 37.049 10.278 37.201 ;
     RECT  36.252 36.895 40.59 37.291 ;
     RECT  9.648 37.201 10.782 37.355 ;
     RECT  33.804 36.311 35.478 37.435 ;
     RECT  36.252 37.291 40.698 37.435 ;
     RECT  33.804 37.435 40.698 37.469 ;
     RECT  10.764 37.355 10.782 37.499 ;
     RECT  2.376 37.037 5.778 37.589 ;
     RECT  34.596 37.469 40.698 37.589 ;
     RECT  2.412 37.589 5.778 37.597 ;
     RECT  6.624 37.037 6.642 37.597 ;
     RECT  2.412 37.597 6.642 37.613 ;
     RECT  9.648 37.355 9.702 37.625 ;
     RECT  2.415 37.613 6.642 37.831 ;
     RECT  34.596 37.589 35.478 37.895 ;
     RECT  9.648 37.625 9.666 38.039 ;
     RECT  2.415 37.831 6.75 38.165 ;
     RECT  36.252 37.589 40.698 38.399 ;
     RECT  2.415 38.165 2.97 38.491 ;
     RECT  36.252 38.399 36.954 38.621 ;
     RECT  37.764 38.399 40.698 38.713 ;
     RECT  3.78 38.165 6.75 38.741 ;
     RECT  37.764 38.713 40.914 38.741 ;
     RECT  34.815 37.895 35.478 38.749 ;
     RECT  36.252 38.621 36.594 38.749 ;
     RECT  2.376 38.491 2.97 38.821 ;
     RECT  2.304 38.821 2.97 38.975 ;
     RECT  2.415 38.975 2.97 39.019 ;
     RECT  3.78 38.741 6.642 39.019 ;
     RECT  37.764 38.741 39.114 39.181 ;
     RECT  33.804 37.469 33.858 39.217 ;
     RECT  34.815 38.749 36.594 39.217 ;
     RECT  33.732 39.217 36.594 39.245 ;
     RECT  33.732 39.245 35.946 39.293 ;
     RECT  33.804 39.293 35.946 39.515 ;
     RECT  37.584 39.181 39.114 39.595 ;
     RECT  40.032 38.741 40.914 39.595 ;
     RECT  2.415 39.019 6.642 39.623 ;
     RECT  19.656 32.737 20.214 39.623 ;
     RECT  37.584 39.595 40.914 39.631 ;
     RECT  43.092 39.523 43.11 39.631 ;
     RECT  20.196 39.623 20.214 39.659 ;
     RECT  36.72 39.631 40.914 39.749 ;
     RECT  42.156 36.715 42.174 39.749 ;
     RECT  2.415 39.623 3.402 39.979 ;
     RECT  43.02 39.631 43.11 40.157 ;
     RECT  2.304 39.979 3.402 40.289 ;
     RECT  34.776 39.515 35.946 40.297 ;
     RECT  33.804 39.515 33.822 40.459 ;
     RECT  2.304 40.289 2.697 40.469 ;
     RECT  34.776 40.297 36.054 40.555 ;
     RECT  24.015 33.007 24.786 40.559 ;
     RECT  36.936 39.749 40.914 40.589 ;
     RECT  4.248 39.623 6.642 40.595 ;
     RECT  36.936 40.589 40.698 40.595 ;
     RECT  38.772 40.595 40.698 40.631 ;
     RECT  7.815 36.959 8.097 40.675 ;
     RECT  4.68 40.595 6.642 40.711 ;
     RECT  7.74 40.675 8.097 40.711 ;
     RECT  33.732 40.459 33.822 40.711 ;
     RECT  34.632 40.555 36.054 40.711 ;
     RECT  36.936 40.595 38.034 40.711 ;
     RECT  2.415 40.469 2.697 40.787 ;
     RECT  4.68 40.711 8.097 40.787 ;
     RECT  13.215 34.385 13.497 40.787 ;
     RECT  18.615 30.407 18.897 40.787 ;
     RECT  24.015 40.559 24.297 40.787 ;
     RECT  29.415 17.681 29.697 40.787 ;
     RECT  4.68 40.787 7.905 40.829 ;
     RECT  33.732 40.711 38.034 40.829 ;
     RECT  39.06 40.631 40.662 40.829 ;
     RECT  4.752 40.829 7.905 40.835 ;
     RECT  5.112 40.835 7.905 40.865 ;
     RECT  33.732 40.829 33.75 40.865 ;
     RECT  34.524 40.829 34.974 40.865 ;
     RECT  35.928 40.829 36.558 40.865 ;
     RECT  37.836 40.829 38.034 40.865 ;
     RECT  39.78 40.829 40.662 40.865 ;
     RECT  3.924 40.801 3.942 40.901 ;
     RECT  5.112 40.865 5.67 40.901 ;
     RECT  6.768 40.865 6.786 40.901 ;
     RECT  34.815 40.865 34.974 40.901 ;
     RECT  35.928 40.865 36.27 40.901 ;
     RECT  38.016 40.865 38.034 40.901 ;
     RECT  42.192 40.441 42.21 40.981 ;
     RECT  5.112 40.901 5.13 41.009 ;
     RECT  39.888 40.865 40.305 41.009 ;
     RECT  42.156 40.981 42.21 41.021 ;
     RECT  2.415 40.787 2.505 41.057 ;
     RECT  7.815 40.865 7.905 41.057 ;
     RECT  13.215 40.787 13.305 41.057 ;
     RECT  18.615 40.787 18.705 41.057 ;
     RECT  24.015 40.787 24.105 41.057 ;
     RECT  29.415 40.787 29.505 41.057 ;
     RECT  34.815 40.901 34.905 41.057 ;
     RECT  40.215 41.009 40.305 41.057 ;
     RECT  43.02 40.157 43.074 41.453 ;
     RECT  0.108 40.981 0.126 41.501 ;
     RECT  42.192 41.021 42.21 41.885 ;
     RECT  43.02 41.453 43.038 42.317 ;
    LAYER M4 ;
     RECT  0.084 0.672 0.137 0.696 ;
     RECT  0.06 0.696 0.137 1.104 ;
     RECT  0.084 1.104 0.137 1.128 ;
     RECT  0.06 1.128 0.137 1.488 ;
     RECT  0.084 1.488 0.137 1.512 ;
     RECT  0.06 1.512 0.137 1.872 ;
     RECT  0.084 1.872 0.137 1.896 ;
     RECT  0.06 1.896 0.137 2.304 ;
     RECT  0.084 2.304 0.137 2.328 ;
     RECT  0.06 2.328 0.137 3.216 ;
     RECT  0.084 3.216 0.137 3.24 ;
     RECT  0.06 3.24 0.137 3.648 ;
     RECT  0.084 3.648 0.137 3.672 ;
     RECT  0.06 3.672 0.137 4.08 ;
     RECT  0.084 4.08 0.137 4.104 ;
     RECT  0.06 4.104 0.137 4.512 ;
     RECT  0.084 4.512 0.137 4.536 ;
     RECT  0.06 4.536 0.137 4.896 ;
     RECT  0.084 4.896 0.137 4.92 ;
     RECT  0.06 4.92 0.137 5.328 ;
     RECT  0.084 5.328 0.137 5.352 ;
     RECT  0.06 5.352 0.137 5.76 ;
     RECT  0.084 5.76 0.137 5.784 ;
     RECT  0.06 5.784 0.137 6.192 ;
     RECT  0.084 6.192 0.137 6.216 ;
     RECT  0.06 6.216 0.137 6.624 ;
     RECT  0.084 6.624 0.137 6.648 ;
     RECT  0.06 6.648 0.137 7.056 ;
     RECT  0.084 7.056 0.137 7.08 ;
     RECT  0.06 7.08 0.137 7.488 ;
     RECT  0.084 7.488 0.137 7.512 ;
     RECT  0.06 7.512 0.137 7.92 ;
     RECT  0.084 7.92 0.137 7.944 ;
     RECT  0.06 7.944 0.137 8.352 ;
     RECT  0.084 8.352 0.137 8.376 ;
     RECT  0.06 8.376 0.137 8.784 ;
     RECT  0.084 8.784 0.137 8.808 ;
     RECT  0.06 8.808 0.137 9.216 ;
     RECT  0.084 9.216 0.137 9.24 ;
     RECT  0.06 9.24 0.137 9.648 ;
     RECT  0.084 9.648 0.137 9.672 ;
     RECT  0.06 9.672 0.137 10.08 ;
     RECT  0.084 10.08 0.137 10.104 ;
     RECT  0.06 10.104 0.137 10.512 ;
     RECT  0.084 10.512 0.137 10.536 ;
     RECT  0.06 10.536 0.137 10.896 ;
     RECT  0.084 10.896 0.137 10.92 ;
     RECT  0.06 10.92 0.137 11.328 ;
     RECT  0.084 11.328 0.137 11.352 ;
     RECT  0.06 11.352 0.137 11.76 ;
     RECT  0.084 11.76 0.137 11.784 ;
     RECT  0.06 11.784 0.137 12.192 ;
     RECT  0.084 12.192 0.137 12.216 ;
     RECT  0.06 12.216 0.137 12.624 ;
     RECT  0.084 12.624 0.137 12.648 ;
     RECT  0.06 12.648 0.137 13.056 ;
     RECT  0.084 13.056 0.137 13.08 ;
     RECT  0.06 13.08 0.137 13.488 ;
     RECT  0.084 13.488 0.137 13.512 ;
     RECT  0.06 13.512 0.137 13.92 ;
     RECT  0.084 13.92 0.137 13.944 ;
     RECT  0.06 13.944 0.137 14.352 ;
     RECT  0.084 14.352 0.137 14.376 ;
     RECT  0.06 14.376 0.137 14.784 ;
     RECT  0.084 14.784 0.137 14.808 ;
     RECT  0.06 14.808 0.137 15.216 ;
     RECT  0.084 15.216 0.137 15.24 ;
     RECT  0.06 15.24 0.137 15.648 ;
     RECT  0.084 15.648 0.137 15.672 ;
     RECT  0.06 15.672 0.137 16.08 ;
     RECT  0.084 16.08 0.137 16.104 ;
     RECT  0.06 16.104 0.137 16.512 ;
     RECT  0.084 16.512 0.137 16.536 ;
     RECT  0.06 16.536 0.137 16.896 ;
     RECT  0.084 16.896 0.137 16.92 ;
     RECT  0.06 16.92 0.137 17.328 ;
     RECT  0.084 17.328 0.137 17.352 ;
     RECT  0.06 17.352 0.137 17.76 ;
     RECT  0.084 17.76 0.137 17.784 ;
     RECT  0.06 17.784 0.137 18.192 ;
     RECT  0.084 18.192 0.137 18.216 ;
     RECT  0.06 18.216 0.137 18.624 ;
     RECT  0.084 18.624 0.137 18.648 ;
     RECT  0.06 18.648 0.137 19.056 ;
     RECT  0.084 19.056 0.137 19.08 ;
     RECT  0.06 19.08 0.137 19.488 ;
     RECT  0.084 19.488 0.137 19.512 ;
     RECT  0.06 19.512 0.137 19.92 ;
     RECT  0.084 19.92 0.137 19.944 ;
     RECT  0.06 19.944 0.137 20.352 ;
     RECT  0.084 20.352 0.137 20.376 ;
     RECT  0.06 20.376 0.137 20.784 ;
     RECT  0.084 20.784 0.137 20.808 ;
     RECT  0.06 20.808 0.137 21.216 ;
     RECT  0.084 21.216 0.137 21.24 ;
     RECT  0.06 21.24 0.137 21.648 ;
     RECT  0.084 21.648 0.137 21.672 ;
     RECT  0.06 21.672 0.137 22.08 ;
     RECT  0.084 22.08 0.137 22.104 ;
     RECT  0.06 22.104 0.137 22.512 ;
     RECT  0.084 22.512 0.137 22.536 ;
     RECT  0.06 22.536 0.137 22.896 ;
     RECT  0.084 22.896 0.137 22.92 ;
     RECT  0.06 22.92 0.137 23.328 ;
     RECT  0.084 23.328 0.137 23.352 ;
     RECT  0.06 23.352 0.137 23.76 ;
     RECT  0.084 23.76 0.137 23.784 ;
     RECT  0.06 23.784 0.137 24.192 ;
     RECT  0.084 24.192 0.137 24.216 ;
     RECT  0.06 24.216 0.137 24.624 ;
     RECT  0.084 24.624 0.137 24.648 ;
     RECT  0.06 24.648 0.137 25.056 ;
     RECT  0.084 25.056 0.137 25.08 ;
     RECT  0.06 25.08 0.137 25.488 ;
     RECT  0.084 25.488 0.137 25.512 ;
     RECT  0.06 25.512 0.137 25.92 ;
     RECT  0.084 25.92 0.137 25.944 ;
     RECT  0.06 25.944 0.137 26.352 ;
     RECT  0.084 26.352 0.137 26.376 ;
     RECT  0.06 26.376 0.137 26.784 ;
     RECT  0.084 26.784 0.137 26.808 ;
     RECT  0.06 26.808 0.137 27.216 ;
     RECT  0.084 27.216 0.137 27.24 ;
     RECT  0.06 27.24 0.137 27.648 ;
     RECT  0.084 27.648 0.137 27.672 ;
     RECT  0.06 27.672 0.137 28.08 ;
     RECT  0.084 28.08 0.137 28.104 ;
     RECT  0.06 28.104 0.137 28.512 ;
     RECT  0.084 28.512 0.137 28.536 ;
     RECT  0.06 28.536 0.137 28.896 ;
     RECT  0.084 28.896 0.137 28.92 ;
     RECT  0.06 28.92 0.137 29.328 ;
     RECT  0.084 29.328 0.137 29.352 ;
     RECT  0.06 29.352 0.137 29.76 ;
     RECT  0.084 29.76 0.137 29.784 ;
     RECT  0.06 29.784 0.137 30.192 ;
     RECT  0.084 30.192 0.137 30.216 ;
     RECT  0.06 30.216 0.137 30.624 ;
     RECT  0.084 30.624 0.137 30.648 ;
     RECT  0.06 30.648 0.137 31.056 ;
     RECT  0.084 31.056 0.137 31.08 ;
     RECT  0.06 31.08 0.137 31.488 ;
     RECT  0.084 31.488 0.137 31.512 ;
     RECT  0.06 31.512 0.137 31.92 ;
     RECT  0.084 31.92 0.137 31.944 ;
     RECT  0.06 31.944 0.137 32.352 ;
     RECT  0.084 32.352 0.137 32.376 ;
     RECT  0.06 32.376 0.137 32.784 ;
     RECT  0.084 32.784 0.137 32.808 ;
     RECT  0.137 1.104 0.173 2.328 ;
     RECT  0.137 3.648 0.173 32.808 ;
     RECT  0.173 1.488 0.209 2.328 ;
     RECT  0.173 4.08 0.209 4.536 ;
     RECT  0.209 4.512 0.569 4.536 ;
     RECT  0.173 7.056 2.293 32.808 ;
     RECT  0.209 1.872 2.408 2.328 ;
     RECT  2.293 7.056 2.408 34.776 ;
     RECT  2.401 37.008 2.408 38.52 ;
     RECT  2.408 1.872 2.512 41.052 ;
     RECT  2.512 1.872 2.704 40.782 ;
     RECT  2.704 1.872 2.765 2.328 ;
     RECT  2.704 27.648 2.765 27.672 ;
     RECT  2.704 31.488 2.765 31.512 ;
     RECT  2.704 32.784 2.765 32.808 ;
     RECT  2.765 1.872 2.801 1.896 ;
     RECT  2.704 24.192 2.801 24.216 ;
     RECT  2.704 25.488 2.801 25.8 ;
     RECT  2.704 37.056 3.557 37.608 ;
     RECT  2.704 34.752 3.697 34.776 ;
     RECT  2.704 39.6 3.841 39.624 ;
     RECT  3.697 34.752 4.165 35.352 ;
     RECT  4.165 34.752 4.201 35.928 ;
     RECT  3.557 37.056 4.597 37.56 ;
     RECT  4.597 37.008 4.645 38.184 ;
     RECT  3.841 39.456 4.645 39.624 ;
     RECT  4.645 37.008 4.691 39.624 ;
     RECT  4.691 37.008 4.701 37.56 ;
     RECT  4.691 38.64 4.781 39.624 ;
     RECT  4.741 40.8 5.245 40.824 ;
     RECT  5.245 40.56 5.825 40.824 ;
     RECT  4.781 38.64 5.861 38.664 ;
     RECT  5.825 40.8 6.473 40.824 ;
     RECT  4.201 34.368 6.517 35.928 ;
     RECT  4.701 37.008 6.517 37.032 ;
     RECT  6.517 34.368 6.604 37.032 ;
     RECT  6.604 34.368 6.833 35.928 ;
     RECT  6.833 34.368 6.901 35.112 ;
     RECT  2.704 7.056 7.808 8.328 ;
     RECT  2.801 25.776 7.808 25.8 ;
     RECT  6.901 33.6 7.808 35.112 ;
     RECT  6.604 37.008 7.808 37.032 ;
     RECT  7.808 2.148 7.912 41.052 ;
     RECT  7.912 2.418 8.104 40.782 ;
     RECT  9.493 36.48 9.577 36.504 ;
     RECT  8.104 25.776 10.213 25.8 ;
     RECT  8.104 33.6 10.253 34.728 ;
     RECT  10.253 33.6 10.259 34.632 ;
     RECT  10.259 33.6 11.765 34.488 ;
     RECT  8.104 7.056 13.208 8.328 ;
     RECT  10.213 25.776 13.208 26.04 ;
     RECT  11.765 34.464 13.208 34.488 ;
     RECT  13.208 2.148 13.312 41.052 ;
     RECT  13.312 2.418 13.504 40.782 ;
     RECT  13.504 34.464 13.715 34.488 ;
     RECT  13.504 32.16 14.243 32.184 ;
     RECT  13.504 30.672 14.757 30.696 ;
     RECT  14.757 30.672 14.819 30.792 ;
     RECT  14.819 30.768 14.861 30.792 ;
     RECT  13.504 7.056 16.409 8.328 ;
     RECT  16.409 7.056 16.841 7.08 ;
     RECT  17.053 28.512 17.137 28.536 ;
     RECT  16.409 8.304 17.381 8.328 ;
     RECT  17.077 27.216 18.313 27.24 ;
     RECT  13.504 25.776 18.608 26.04 ;
     RECT  18.313 27.072 18.608 27.24 ;
     RECT  18.608 2.148 18.712 41.052 ;
     RECT  18.712 2.418 18.904 40.782 ;
     RECT  18.904 25.584 21.053 26.04 ;
     RECT  21.053 25.584 21.089 25.848 ;
     RECT  21.229 23.376 21.683 23.4 ;
     RECT  18.904 27.072 22.381 27.096 ;
     RECT  21.637 22.368 22.852 22.392 ;
     RECT  22.852 22.32 23.372 22.392 ;
     RECT  23.372 22.32 24.008 22.632 ;
     RECT  21.089 25.824 24.008 25.848 ;
     RECT  22.381 27.072 24.008 27.192 ;
     RECT  24.008 2.148 24.112 41.052 ;
     RECT  24.112 2.418 24.304 40.782 ;
     RECT  24.304 20.688 24.515 20.712 ;
     RECT  24.304 22.32 24.515 22.44 ;
     RECT  24.304 19.344 25.805 19.368 ;
     RECT  27.277 17.088 27.361 17.112 ;
     RECT  27.301 15.552 28.789 15.576 ;
     RECT  28.789 15.456 29.408 15.576 ;
     RECT  24.304 27.072 29.408 27.336 ;
     RECT  29.408 2.148 29.512 41.052 ;
     RECT  29.512 2.418 29.704 40.782 ;
     RECT  29.704 27.072 30.275 27.192 ;
     RECT  29.704 14.208 30.349 14.232 ;
     RECT  29.704 30.384 31.057 30.84 ;
     RECT  31.057 30.384 31.345 31.32 ;
     RECT  31.345 30.288 31.385 31.32 ;
     RECT  29.704 15.456 32.209 15.48 ;
     RECT  31.385 30.288 32.425 30.312 ;
     RECT  31.385 31.296 32.425 31.32 ;
     RECT  31.741 12.144 32.469 12.168 ;
     RECT  32.469 11.52 32.531 12.168 ;
     RECT  32.425 30.288 33.685 31.32 ;
     RECT  30.275 27.072 33.721 27.096 ;
     RECT  33.685 30.288 33.731 32.568 ;
     RECT  33.692 20.736 33.733 20.76 ;
     RECT  33.692 22.272 33.733 22.296 ;
     RECT  33.692 39.264 33.733 39.288 ;
     RECT  33.721 40.464 33.733 40.488 ;
     RECT  33.721 26.208 33.761 27.096 ;
     RECT  33.731 30.288 33.761 30.84 ;
     RECT  33.731 31.968 33.772 32.568 ;
     RECT  32.531 11.52 33.779 11.544 ;
     RECT  33.692 14.208 33.779 14.232 ;
     RECT  33.733 20.4 33.779 20.76 ;
     RECT  33.733 21.744 33.779 22.296 ;
     RECT  33.733 39.264 33.779 40.488 ;
     RECT  33.721 18.24 33.805 18.264 ;
     RECT  33.685 33.888 34.405 34.248 ;
     RECT  32.209 15.312 34.613 15.48 ;
     RECT  33.779 40.032 34.621 40.488 ;
     RECT  33.692 17.088 34.645 17.112 ;
     RECT  34.613 15.312 34.808 15.96 ;
     RECT  34.645 17.088 34.808 17.448 ;
     RECT  33.779 20.4 34.808 20.424 ;
     RECT  33.779 21.744 34.808 21.768 ;
     RECT  33.721 23.952 34.808 23.976 ;
     RECT  33.761 26.208 34.808 26.232 ;
     RECT  33.721 28.8 34.808 28.824 ;
     RECT  33.761 30.288 34.808 30.408 ;
     RECT  33.772 31.968 34.808 31.992 ;
     RECT  34.405 33.888 34.808 35.016 ;
     RECT  33.692 36 34.808 36.024 ;
     RECT  33.733 37.44 34.808 37.464 ;
     RECT  34.621 40.032 34.808 40.584 ;
     RECT  34.808 2.148 34.912 41.052 ;
     RECT  34.912 2.418 35.104 40.782 ;
     RECT  35.104 28.8 35.273 28.824 ;
     RECT  35.104 20.4 35.309 20.424 ;
     RECT  35.104 30.192 35.309 30.408 ;
     RECT  35.104 33.888 35.309 35.352 ;
     RECT  35.104 10.464 35.315 11.256 ;
     RECT  35.104 13.056 35.315 13.08 ;
     RECT  35.104 23.52 35.315 23.976 ;
     RECT  35.104 39.072 35.315 40.584 ;
     RECT  35.104 14.832 35.345 14.856 ;
     RECT  35.104 25.104 35.345 25.128 ;
     RECT  35.315 39.072 35.345 40.056 ;
     RECT  35.315 23.52 35.356 23.544 ;
     RECT  35.104 37.488 35.356 37.512 ;
     RECT  35.104 21.648 36.097 21.768 ;
     RECT  36.524 28.752 36.565 28.776 ;
     RECT  36.565 28.752 36.707 29.064 ;
     RECT  35.309 30.192 36.707 30.312 ;
     RECT  36.565 33.024 36.707 33.048 ;
     RECT  35.104 17.424 36.781 17.448 ;
     RECT  35.104 18.48 36.781 18.504 ;
     RECT  36.781 17.424 36.821 18.504 ;
     RECT  36.097 21.648 36.851 22.632 ;
     RECT  36.821 17.424 36.885 17.832 ;
     RECT  35.315 10.464 36.889 10.488 ;
     RECT  35.104 26.64 36.889 26.664 ;
     RECT  36.86 24.912 36.901 24.936 ;
     RECT  35.345 39.072 36.901 39.864 ;
     RECT  35.104 31.92 36.925 31.944 ;
     RECT  36.901 38.592 36.925 39.864 ;
     RECT  36.889 26.208 36.929 26.664 ;
     RECT  36.707 30.192 36.929 30.216 ;
     RECT  36.901 24.48 36.947 24.936 ;
     RECT  36.925 38.592 36.947 39.912 ;
     RECT  36.908 12.72 36.949 12.744 ;
     RECT  36.925 31.296 36.965 31.944 ;
     RECT  36.889 36.48 36.973 36.504 ;
     RECT  36.901 22.752 36.988 22.968 ;
     RECT  35.309 34.704 36.988 35.352 ;
     RECT  36.947 38.592 36.988 38.616 ;
     RECT  36.851 21.648 36.993 21.672 ;
     RECT  36.889 10.464 36.995 10.728 ;
     RECT  36.949 12.528 36.995 12.744 ;
     RECT  36.908 14.304 36.995 14.328 ;
     RECT  36.885 17.568 36.995 17.832 ;
     RECT  36.421 1.824 37.285 1.848 ;
     RECT  36.997 3.984 37.393 4.008 ;
     RECT  36.925 33.264 37.573 33.288 ;
     RECT  36.988 34.704 37.573 34.728 ;
     RECT  37.573 33.264 38.492 34.728 ;
     RECT  36.965 31.296 38.509 31.32 ;
     RECT  36.889 28.656 38.533 28.68 ;
     RECT  38.485 14.112 38.545 14.136 ;
     RECT  38.533 38.064 38.545 38.088 ;
     RECT  36.995 10.464 38.549 10.488 ;
     RECT  36.995 12.528 38.549 12.552 ;
     RECT  35.104 15.936 38.549 15.96 ;
     RECT  36.995 17.568 38.549 17.592 ;
     RECT  36.889 19.344 38.549 19.368 ;
     RECT  38.465 21.072 38.549 21.096 ;
     RECT  36.947 24.48 38.549 24.504 ;
     RECT  38.509 30.768 38.549 31.32 ;
     RECT  38.492 33.024 38.549 34.728 ;
     RECT  36.947 39.696 38.549 39.912 ;
     RECT  38.545 14.112 38.572 14.856 ;
     RECT  36.988 22.752 38.572 22.776 ;
     RECT  38.533 27.84 38.579 29.448 ;
     RECT  38.549 33.024 38.579 34.632 ;
     RECT  38.492 36.24 38.579 36.264 ;
     RECT  36.929 26.208 38.613 26.232 ;
     RECT  38.579 27.84 38.62 27.864 ;
     RECT  38.579 29.424 38.62 29.448 ;
     RECT  38.545 38.064 38.62 38.184 ;
     RECT  38.549 30.768 38.621 30.792 ;
     RECT  38.549 39.888 38.627 39.912 ;
     RECT  38.62 38.16 38.629 38.184 ;
     RECT  38.572 14.832 38.657 14.856 ;
     RECT  38.579 34.608 38.693 34.632 ;
     RECT  37.285 1.296 39.013 1.848 ;
     RECT  39.013 0.768 40.208 1.848 ;
     RECT  37.393 3.552 40.208 4.008 ;
     RECT  40.208 0.768 40.312 41.052 ;
     RECT  40.312 0.768 40.504 40.782 ;
     RECT  40.504 0.768 41.605 2.376 ;
     RECT  40.504 3.456 41.605 4.008 ;
     RECT  41.605 5.04 42.109 5.064 ;
     RECT  41.605 0.768 42.145 4.008 ;
     RECT  42.109 5.04 42.145 5.592 ;
     RECT  42.109 7.2 42.145 7.224 ;
     RECT  42.109 18.72 42.145 18.744 ;
     RECT  40.504 40.56 42.145 40.584 ;
     RECT  42.145 10.176 42.181 41.016 ;
     RECT  42.181 10.176 43.009 41.88 ;
     RECT  42.145 0.768 43.081 5.592 ;
     RECT  42.145 6.672 43.081 7.224 ;
     RECT  43.081 0.768 43.116 0.792 ;
     RECT  43.081 0.792 43.164 1.296 ;
     RECT  43.081 1.296 43.116 1.32 ;
     RECT  43.081 1.32 43.164 1.824 ;
     RECT  43.081 1.824 43.116 1.848 ;
     RECT  43.081 1.848 43.164 2.352 ;
     RECT  43.081 2.352 43.116 2.376 ;
     RECT  43.081 2.376 43.164 2.88 ;
     RECT  43.081 2.88 43.116 2.904 ;
     RECT  43.081 2.904 43.164 3.456 ;
     RECT  43.081 3.456 43.116 3.48 ;
     RECT  43.081 3.48 43.164 3.984 ;
     RECT  43.081 3.984 43.116 4.008 ;
     RECT  43.081 4.008 43.164 4.512 ;
     RECT  43.081 4.512 43.116 4.536 ;
     RECT  43.081 4.536 43.164 5.04 ;
     RECT  43.081 5.04 43.116 5.064 ;
     RECT  43.081 5.064 43.164 5.568 ;
     RECT  43.081 5.568 43.116 5.592 ;
     RECT  43.081 5.592 43.164 6.096 ;
     RECT  43.081 6.096 43.116 6.12 ;
     RECT  43.081 6.12 43.164 6.672 ;
     RECT  43.081 6.672 43.116 6.696 ;
     RECT  43.081 6.696 43.164 7.2 ;
     RECT  43.081 7.2 43.116 7.224 ;
     RECT  43.081 7.224 43.164 7.728 ;
     RECT  43.081 7.728 43.116 7.752 ;
     RECT  43.009 10.176 43.116 10.2 ;
     RECT  43.009 10.2 43.164 10.608 ;
     RECT  43.009 10.608 43.116 10.632 ;
     RECT  43.009 10.632 43.164 10.992 ;
     RECT  43.009 10.992 43.116 11.016 ;
     RECT  43.009 11.016 43.164 11.376 ;
     RECT  43.009 11.376 43.116 11.4 ;
     RECT  43.009 11.4 43.164 11.808 ;
     RECT  43.009 11.808 43.116 11.832 ;
     RECT  43.009 11.832 43.164 12.72 ;
     RECT  43.009 12.72 43.116 12.744 ;
     RECT  43.009 12.744 43.164 13.152 ;
     RECT  43.009 13.152 43.116 13.176 ;
     RECT  43.009 13.176 43.164 13.536 ;
     RECT  43.009 13.536 43.116 13.56 ;
     RECT  43.009 13.56 43.164 13.968 ;
     RECT  43.009 13.968 43.116 13.992 ;
     RECT  43.009 13.992 43.164 14.4 ;
     RECT  43.009 14.4 43.116 14.424 ;
     RECT  43.009 14.424 43.164 14.832 ;
     RECT  43.009 14.832 43.116 14.856 ;
     RECT  43.009 14.856 43.164 15.264 ;
     RECT  43.009 15.264 43.116 15.288 ;
     RECT  43.009 15.288 43.164 15.696 ;
     RECT  43.009 15.696 43.116 15.72 ;
     RECT  43.009 15.72 43.164 16.128 ;
     RECT  43.009 16.128 43.116 16.152 ;
     RECT  43.009 16.152 43.164 16.56 ;
     RECT  43.009 16.56 43.116 16.584 ;
     RECT  43.009 16.584 43.164 16.992 ;
     RECT  43.009 16.992 43.116 17.016 ;
     RECT  43.009 17.016 43.164 17.424 ;
     RECT  43.009 17.424 43.116 17.448 ;
     RECT  43.009 17.448 43.164 17.856 ;
     RECT  43.009 17.856 43.116 17.88 ;
     RECT  43.009 17.88 43.164 18.288 ;
     RECT  43.009 18.288 43.116 18.312 ;
     RECT  43.009 18.312 43.164 18.72 ;
     RECT  43.009 18.72 43.116 18.744 ;
     RECT  43.009 18.744 43.164 19.152 ;
     RECT  43.009 19.152 43.116 19.176 ;
     RECT  43.009 19.176 43.164 19.536 ;
     RECT  43.009 19.536 43.116 19.56 ;
     RECT  43.009 19.56 43.164 19.968 ;
     RECT  43.009 19.968 43.116 19.992 ;
     RECT  43.009 19.992 43.164 20.4 ;
     RECT  43.009 20.4 43.116 20.424 ;
     RECT  43.009 20.424 43.164 20.832 ;
     RECT  43.009 20.832 43.116 20.856 ;
     RECT  43.009 20.856 43.164 21.264 ;
     RECT  43.009 21.264 43.116 21.288 ;
     RECT  43.009 21.288 43.164 21.696 ;
     RECT  43.009 21.696 43.116 21.72 ;
     RECT  43.009 21.72 43.164 22.128 ;
     RECT  43.009 22.128 43.116 22.152 ;
     RECT  43.009 22.152 43.164 22.56 ;
     RECT  43.009 22.56 43.116 22.584 ;
     RECT  43.009 22.584 43.164 22.992 ;
     RECT  43.009 22.992 43.116 23.016 ;
     RECT  43.009 23.016 43.164 23.424 ;
     RECT  43.009 23.424 43.116 23.448 ;
     RECT  43.009 23.448 43.164 23.856 ;
     RECT  43.009 23.856 43.116 23.88 ;
     RECT  43.009 23.88 43.164 24.288 ;
     RECT  43.009 24.288 43.116 24.312 ;
     RECT  43.009 24.312 43.164 24.72 ;
     RECT  43.009 24.72 43.116 24.744 ;
     RECT  43.009 24.744 43.164 25.152 ;
     RECT  43.009 25.152 43.116 25.176 ;
     RECT  43.009 25.176 43.164 25.536 ;
     RECT  43.009 25.536 43.116 25.56 ;
     RECT  43.009 25.56 43.164 25.968 ;
     RECT  43.009 25.968 43.116 25.992 ;
     RECT  43.009 25.992 43.164 26.4 ;
     RECT  43.009 26.4 43.116 26.424 ;
     RECT  43.009 26.424 43.164 26.832 ;
     RECT  43.009 26.832 43.116 26.856 ;
     RECT  43.009 26.856 43.164 27.264 ;
     RECT  43.009 27.264 43.116 27.288 ;
     RECT  43.009 27.288 43.164 27.696 ;
     RECT  43.009 27.696 43.116 27.72 ;
     RECT  43.009 27.72 43.164 28.128 ;
     RECT  43.009 28.128 43.116 28.152 ;
     RECT  43.009 28.152 43.164 28.56 ;
     RECT  43.009 28.56 43.116 28.584 ;
     RECT  43.009 28.584 43.164 28.992 ;
     RECT  43.009 28.992 43.116 29.016 ;
     RECT  43.009 29.016 43.164 29.424 ;
     RECT  43.009 29.424 43.116 29.448 ;
     RECT  43.009 29.448 43.164 29.856 ;
     RECT  43.009 29.856 43.116 29.88 ;
     RECT  43.009 29.88 43.164 30.288 ;
     RECT  43.009 30.288 43.116 30.312 ;
     RECT  43.009 30.312 43.164 30.72 ;
     RECT  43.009 30.72 43.116 30.744 ;
     RECT  43.009 30.744 43.164 31.152 ;
     RECT  43.009 31.152 43.116 31.176 ;
     RECT  43.009 31.176 43.164 31.536 ;
     RECT  43.009 31.536 43.116 31.56 ;
     RECT  43.009 31.56 43.164 31.968 ;
     RECT  43.009 31.968 43.116 31.992 ;
     RECT  43.009 31.992 43.164 32.4 ;
     RECT  43.009 32.4 43.116 32.424 ;
     RECT  43.009 32.424 43.164 32.832 ;
     RECT  43.009 32.832 43.116 32.856 ;
     RECT  43.009 32.856 43.164 33.264 ;
     RECT  43.009 33.264 43.116 33.288 ;
     RECT  43.009 33.288 43.164 33.696 ;
     RECT  43.009 33.696 43.116 33.72 ;
     RECT  43.009 33.72 43.164 34.128 ;
     RECT  43.009 34.128 43.116 34.152 ;
     RECT  43.009 34.152 43.164 34.56 ;
     RECT  43.009 34.56 43.116 34.584 ;
     RECT  43.009 34.584 43.164 34.992 ;
     RECT  43.009 34.992 43.116 35.016 ;
     RECT  43.009 35.016 43.164 35.424 ;
     RECT  43.009 35.424 43.116 35.448 ;
     RECT  43.009 35.448 43.164 35.856 ;
     RECT  43.009 35.856 43.116 35.88 ;
     RECT  43.009 35.88 43.164 36.288 ;
     RECT  43.009 36.288 43.116 36.312 ;
     RECT  43.009 36.312 43.164 36.72 ;
     RECT  43.009 36.72 43.116 36.744 ;
     RECT  43.009 36.744 43.164 37.152 ;
     RECT  43.009 37.152 43.116 37.176 ;
     RECT  43.009 37.176 43.164 37.536 ;
     RECT  43.009 37.536 43.116 37.56 ;
     RECT  43.009 37.56 43.164 37.968 ;
     RECT  43.009 37.968 43.116 37.992 ;
     RECT  43.009 37.992 43.164 38.4 ;
     RECT  43.009 38.4 43.116 38.424 ;
     RECT  43.009 38.424 43.164 38.832 ;
     RECT  43.009 38.832 43.116 38.856 ;
     RECT  43.009 38.856 43.164 39.264 ;
     RECT  43.009 39.264 43.116 39.288 ;
     RECT  43.009 39.288 43.164 39.696 ;
     RECT  43.009 39.696 43.116 39.72 ;
     RECT  43.009 39.72 43.164 40.128 ;
     RECT  43.009 40.128 43.116 40.152 ;
     RECT  43.009 40.152 43.164 40.56 ;
     RECT  43.009 40.56 43.116 40.584 ;
     RECT  43.009 40.584 43.164 40.992 ;
     RECT  43.009 40.992 43.116 41.016 ;
     RECT  43.009 41.016 43.164 41.424 ;
     RECT  43.009 41.424 43.116 41.448 ;
     RECT  43.009 41.448 43.164 41.856 ;
     RECT  43.009 41.856 43.116 41.88 ;
     RECT  43.009 41.88 43.164 42.288 ;
     RECT  43.009 42.288 43.116 42.312 ;
    LAYER M5 ;
     RECT  2.4 2.137 2.52 2.151 ;
     RECT  7.8 2.137 7.92 2.151 ;
     RECT  13.2 2.137 13.32 2.151 ;
     RECT  18.6 2.137 18.72 2.151 ;
     RECT  24 2.137 24.12 2.151 ;
     RECT  29.4 2.137 29.52 2.151 ;
     RECT  34.8 2.137 34.92 2.151 ;
     RECT  40.2 2.137 40.32 2.151 ;
     RECT  34.8 2.151 35.112 10.453 ;
     RECT  32.496 11.509 32.52 12.179 ;
     RECT  38.496 12.517 38.52 14.147 ;
     RECT  29.4 2.151 29.712 14.197 ;
     RECT  34.8 10.453 35.304 14.867 ;
     RECT  29.4 14.197 30.312 15.491 ;
     RECT  33.744 11.509 33.768 15.491 ;
     RECT  34.8 14.867 35.112 15.925 ;
     RECT  34.656 15.925 35.112 17.077 ;
     RECT  27.312 15.541 27.336 17.123 ;
     RECT  36.96 10.693 36.984 17.413 ;
     RECT  33.744 17.077 35.112 17.459 ;
     RECT  36.816 17.413 36.984 17.843 ;
     RECT  33.744 17.459 33.768 18.275 ;
     RECT  24 2.151 24.312 19.333 ;
     RECT  34.8 17.459 35.112 21.637 ;
     RECT  36.816 17.843 36.84 21.637 ;
     RECT  33.744 20.389 33.768 22.307 ;
     RECT  24 19.333 24.504 22.451 ;
     RECT  24 22.451 24.312 22.597 ;
     RECT  36.816 21.637 36.936 22.597 ;
     RECT  38.496 21.061 38.52 22.787 ;
     RECT  21.648 22.357 21.672 23.411 ;
     RECT  36.576 22.597 36.936 24.947 ;
     RECT  34.8 21.637 35.304 25.139 ;
     RECT  19.92 25.621 19.944 27.107 ;
     RECT  29.4 15.491 29.712 27.157 ;
     RECT  23.424 22.597 24.312 27.203 ;
     RECT  17.088 27.205 17.112 28.547 ;
     RECT  34.8 25.139 35.112 28.789 ;
     RECT  36.576 24.947 36.6 29.029 ;
     RECT  36.576 29.029 36.696 29.075 ;
     RECT  38.544 26.197 38.568 29.459 ;
     RECT  29.4 27.157 30.264 30.373 ;
     RECT  34.704 28.789 35.112 30.419 ;
     RECT  13.2 2.151 13.512 30.661 ;
     RECT  13.2 30.661 14.808 30.803 ;
     RECT  29.4 30.373 30.504 30.851 ;
     RECT  13.2 30.803 14.232 32.195 ;
     RECT  36.672 29.075 36.696 33.013 ;
     RECT  36.576 33.013 36.696 33.059 ;
     RECT  2.4 2.151 2.712 33.589 ;
     RECT  7.8 2.151 8.112 33.589 ;
     RECT  33.696 31.285 33.72 34.259 ;
     RECT  10.224 26.005 10.248 34.357 ;
     RECT  13.2 32.195 13.704 34.499 ;
     RECT  6.912 33.589 8.112 34.597 ;
     RECT  9.504 34.357 10.248 34.643 ;
     RECT  34.8 30.419 35.112 34.693 ;
     RECT  2.304 33.589 2.712 34.787 ;
     RECT  6.768 34.597 8.112 34.837 ;
     RECT  36.576 33.059 36.6 35.027 ;
     RECT  4.272 34.741 4.296 35.123 ;
     RECT  6.528 34.837 8.112 35.123 ;
     RECT  0.192 25.765 0.216 35.507 ;
     RECT  6.528 35.123 6.552 36.275 ;
     RECT  9.504 34.643 9.528 36.515 ;
     RECT  36.912 35.317 36.936 36.515 ;
     RECT  3.84 35.317 4.2 36.997 ;
     RECT  3.84 36.997 4.632 37.571 ;
     RECT  38.544 33.013 38.568 38.099 ;
     RECT  4.656 38.149 4.68 38.819 ;
     RECT  36.912 38.581 36.936 39.731 ;
     RECT  38.592 38.149 38.616 39.923 ;
     RECT  33.744 35.989 33.768 40.499 ;
     RECT  34.8 34.693 35.304 40.595 ;
     RECT  2.4 34.787 2.712 41.049 ;
     RECT  7.8 35.123 8.112 41.049 ;
     RECT  13.2 34.499 13.512 41.049 ;
     RECT  18.6 2.151 18.912 41.049 ;
     RECT  24 27.203 24.312 41.049 ;
     RECT  29.4 30.851 29.712 41.049 ;
     RECT  34.8 40.595 35.112 41.049 ;
     RECT  40.2 2.151 40.512 41.049 ;
     RECT  2.4 41.049 2.52 41.063 ;
     RECT  7.8 41.049 7.92 41.063 ;
     RECT  13.2 41.049 13.32 41.063 ;
     RECT  18.6 41.049 18.72 41.063 ;
     RECT  24 41.049 24.12 41.063 ;
     RECT  29.4 41.049 29.52 41.063 ;
     RECT  34.8 41.049 34.92 41.063 ;
     RECT  40.2 41.049 40.32 41.063 ;
     RECT  32.52 11.509 33.744 12.179 ;
     RECT  33.768 11.509 34.8 15.491 ;
     RECT  36.984 12.517 38.496 14.147 ;
     RECT  34.656 15.491 34.8 15.925 ;
     RECT  33.768 17.459 34.8 18.275 ;
     RECT  33.768 20.389 34.8 22.307 ;
     RECT  35.304 21.637 36.816 22.597 ;
     RECT  35.304 22.597 36.576 25.139 ;
     RECT  35.112 25.139 36.576 29.075 ;
     RECT  18.912 25.621 19.92 27.107 ;
     RECT  17.112 27.205 18.6 28.547 ;
     RECT  34.704 30.419 34.8 31.285 ;
     RECT  33.72 31.285 34.8 34.259 ;
     RECT  35.112 33.013 36.576 34.693 ;
     RECT  8.112 34.357 9.504 36.515 ;
     RECT  35.304 34.693 36.576 35.027 ;
     RECT  6.552 35.123 7.8 36.275 ;
     RECT  2.712 35.317 3.84 37.571 ;
     RECT  33.768 35.989 34.8 40.499 ;
  END
END ot_s81_mx4_rq
END LIBRARY
